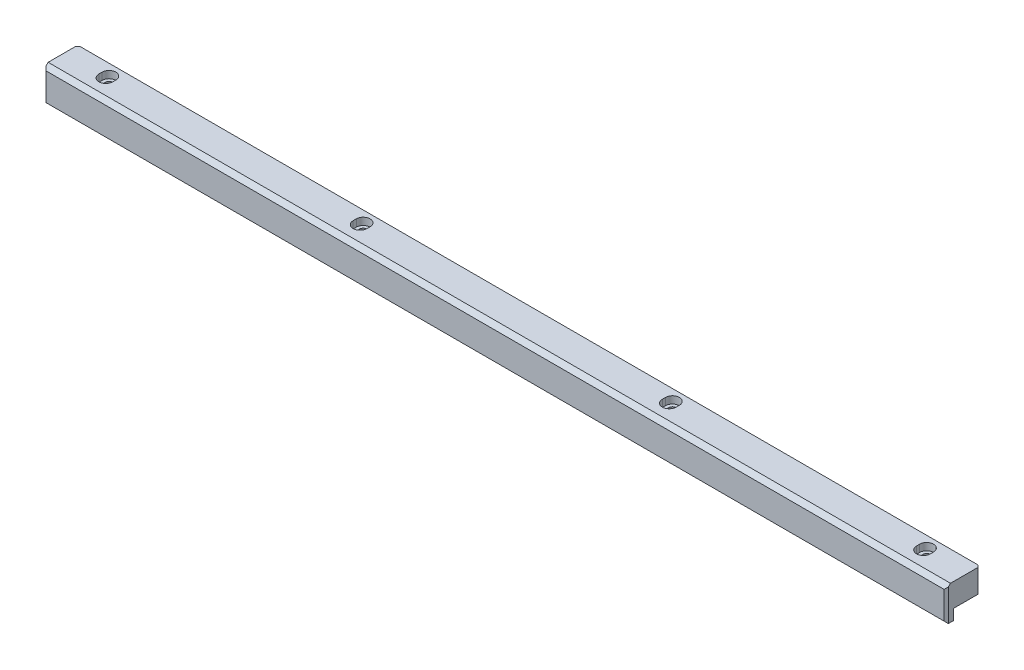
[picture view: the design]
ISO-10303-21;
HEADER;
FILE_DESCRIPTION(('STEP AP214'),'2;1');
FILE_NAME('part.step','',(''),(''),'','','');
FILE_SCHEMA(('AUTOMOTIVE_DESIGN { 1 0 10303 214 1 1 1 1 }'));
ENDSEC;
DATA;
#1=APPLICATION_CONTEXT('core data for automotive mechanical design processes');
#2=APPLICATION_PROTOCOL_DEFINITION('international standard','automotive_design',2000,#1);
#3=PRODUCT_CONTEXT('',#1,'mechanical');
#4=PRODUCT('Part','Part','',(#3));
#5=PRODUCT_RELATED_PRODUCT_CATEGORY('part','',(#4));
#6=PRODUCT_DEFINITION_FORMATION('','',#4);
#7=PRODUCT_DEFINITION_CONTEXT('part definition',#1,'design');
#8=PRODUCT_DEFINITION('design','',#6,#7);
#9=PRODUCT_DEFINITION_SHAPE('','',#8);
#10=(LENGTH_UNIT() NAMED_UNIT(*) SI_UNIT(.MILLI.,.METRE.));
#11=(NAMED_UNIT(*) PLANE_ANGLE_UNIT() SI_UNIT($,.RADIAN.));
#12=(NAMED_UNIT(*) SI_UNIT($,.STERADIAN.) SOLID_ANGLE_UNIT());
#13=UNCERTAINTY_MEASURE_WITH_UNIT(LENGTH_MEASURE(1.E-05),#10,'distance_accuracy_value','');
#14=(GEOMETRIC_REPRESENTATION_CONTEXT(3) GLOBAL_UNCERTAINTY_ASSIGNED_CONTEXT((#13)) GLOBAL_UNIT_ASSIGNED_CONTEXT((#10,
#11,#12)) REPRESENTATION_CONTEXT('',''));
#15=CARTESIAN_POINT('',(0.,0.,0.));
#16=DIRECTION('',(0.,0.,1.));
#17=DIRECTION('',(1.,0.,0.));
#18=AXIS2_PLACEMENT_3D('',#15,#16,#17);
#19=CARTESIAN_POINT('',(0.,16.,0.));
#20=DIRECTION('',(0.,1.,0.));
#21=DIRECTION('',(0.,0.,1.));
#22=AXIS2_PLACEMENT_3D('',#19,#20,#21);
#23=PLANE('',#22);
#24=DIRECTION('',(0.,0.,-1.));
#25=VECTOR('',#24,1.);
#26=CARTESIAN_POINT('',(189.75,16.,-1.25));
#27=LINE('',#26,#25);
#28=CARTESIAN_POINT('',(189.75,16.,-1.25));
#29=VERTEX_POINT('',#28);
#30=CARTESIAN_POINT('',(189.75,16.,-2.75));
#31=VERTEX_POINT('',#30);
#32=EDGE_CURVE('E654',#29,#31,#27,.T.);
#33=ORIENTED_EDGE('',*,*,#32,.T.);
#34=CARTESIAN_POINT('',(193.,16.,-2.75));
#35=DIRECTION('',(0.,1.,0.));
#36=DIRECTION('',(0.,0.,1.));
#37=AXIS2_PLACEMENT_3D('',#34,#35,#36);
#38=CIRCLE('',#37,3.25);
#39=CARTESIAN_POINT('',(196.25,16.,-2.75));
#40=VERTEX_POINT('',#39);
#41=EDGE_CURVE('E674',#40,#31,#38,.T.);
#42=ORIENTED_EDGE('',*,*,#41,.F.);
#43=DIRECTION('',(0.,0.,-1.));
#44=VECTOR('',#43,1.);
#45=CARTESIAN_POINT('',(196.25,16.,-1.25));
#46=LINE('',#45,#44);
#47=CARTESIAN_POINT('',(196.25,16.,-1.25));
#48=VERTEX_POINT('',#47);
#49=EDGE_CURVE('E640',#48,#40,#46,.T.);
#50=ORIENTED_EDGE('',*,*,#49,.F.);
#51=CARTESIAN_POINT('',(193.,16.,-1.25));
#52=DIRECTION('',(0.,1.,0.));
#53=DIRECTION('',(0.,0.,1.));
#54=AXIS2_PLACEMENT_3D('',#51,#52,#53);
#55=CIRCLE('',#54,3.25);
#56=EDGE_CURVE('E629',#29,#48,#55,.T.);
#57=ORIENTED_EDGE('',*,*,#56,.F.);
#58=EDGE_LOOP('',(#33,#42,#50,#57));
#59=FACE_BOUND('',#58,.T.);
#60=DIRECTION('',(0.,0.,-1.));
#61=VECTOR('',#60,1.);
#62=CARTESIAN_POINT('',(76.2499999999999,16.,-1.24999999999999));
#63=LINE('',#62,#61);
#64=CARTESIAN_POINT('',(76.2499999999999,16.,-1.24999999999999));
#65=VERTEX_POINT('',#64);
#66=CARTESIAN_POINT('',(76.2499999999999,16.,-2.74999999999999));
#67=VERTEX_POINT('',#66);
#68=EDGE_CURVE('E828',#65,#67,#63,.T.);
#69=ORIENTED_EDGE('',*,*,#68,.F.);
#70=CARTESIAN_POINT('',(72.9999999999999,16.,-1.24999999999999));
#71=DIRECTION('',(0.,1.,0.));
#72=DIRECTION('',(0.,0.,1.));
#73=AXIS2_PLACEMENT_3D('',#70,#71,#72);
#74=CIRCLE('',#73,3.25);
#75=CARTESIAN_POINT('',(69.7499999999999,16.,-1.24999999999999));
#76=VERTEX_POINT('',#75);
#77=EDGE_CURVE('E859',#76,#65,#74,.T.);
#78=ORIENTED_EDGE('',*,*,#77,.F.);
#79=DIRECTION('',(0.,0.,-1.));
#80=VECTOR('',#79,1.);
#81=CARTESIAN_POINT('',(69.7499999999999,16.,-1.24999999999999));
#82=LINE('',#81,#80);
#83=CARTESIAN_POINT('',(69.7499999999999,16.,-2.74999999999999));
#84=VERTEX_POINT('',#83);
#85=EDGE_CURVE('E844',#76,#84,#82,.T.);
#86=ORIENTED_EDGE('',*,*,#85,.T.);
#87=CARTESIAN_POINT('',(72.9999999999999,16.,-2.74999999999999));
#88=DIRECTION('',(0.,1.,0.));
#89=DIRECTION('',(0.,0.,1.));
#90=AXIS2_PLACEMENT_3D('',#87,#88,#89);
#91=CIRCLE('',#90,3.25);
#92=EDGE_CURVE('E882',#67,#84,#91,.T.);
#93=ORIENTED_EDGE('',*,*,#92,.F.);
#94=EDGE_LOOP('',(#69,#78,#86,#93));
#95=FACE_BOUND('',#94,.T.);
#96=DIRECTION('',(0.,0.,-1.));
#97=VECTOR('',#96,1.);
#98=CARTESIAN_POINT('',(213.,16.,-8.));
#99=LINE('',#98,#97);
#100=CARTESIAN_POINT('',(213.,16.,6.00000000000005));
#101=VERTEX_POINT('',#100);
#102=CARTESIAN_POINT('',(213.,16.,-6.99999999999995));
#103=VERTEX_POINT('',#102);
#104=EDGE_CURVE('E924',#101,#103,#99,.T.);
#105=ORIENTED_EDGE('',*,*,#104,.T.);
#106=DIRECTION('',(0.707106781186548,0.,0.707106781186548));
#107=VECTOR('',#106,1.);
#108=CARTESIAN_POINT('',(110.,16.,-110.));
#109=LINE('',#108,#107);
#110=CARTESIAN_POINT('',(212.,16.,-8.));
#111=VERTEX_POINT('',#110);
#112=EDGE_CURVE('E1050',#103,#111,#109,.F.);
#113=ORIENTED_EDGE('',*,*,#112,.T.);
#114=DIRECTION('',(-1.,0.,0.));
#115=VECTOR('',#114,1.);
#116=CARTESIAN_POINT('',(-213.,16.,-8.));
#117=LINE('',#116,#115);
#118=CARTESIAN_POINT('',(-212.,16.,-8.));
#119=VERTEX_POINT('',#118);
#120=EDGE_CURVE('E928',#111,#119,#117,.T.);
#121=ORIENTED_EDGE('',*,*,#120,.T.);
#122=DIRECTION('',(0.707106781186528,0.,-0.707106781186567));
#123=VECTOR('',#122,1.);
#124=CARTESIAN_POINT('',(-110.000000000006,16.,-110.));
#125=LINE('',#124,#123);
#126=CARTESIAN_POINT('',(-213.,16.,-7.));
#127=VERTEX_POINT('',#126);
#128=EDGE_CURVE('E1047',#119,#127,#125,.F.);
#129=ORIENTED_EDGE('',*,*,#128,.T.);
#130=DIRECTION('',(0.,0.,1.));
#131=VECTOR('',#130,1.);
#132=CARTESIAN_POINT('',(-213.,16.,-8.));
#133=LINE('',#132,#131);
#134=CARTESIAN_POINT('',(-213.,16.,6.00000000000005));
#135=VERTEX_POINT('',#134);
#136=EDGE_CURVE('E933',#127,#135,#133,.T.);
#137=ORIENTED_EDGE('',*,*,#136,.T.);
#138=DIRECTION('',(1.,0.,0.));
#139=VECTOR('',#138,1.);
#140=CARTESIAN_POINT('',(213.,16.,6.00000000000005));
#141=LINE('',#140,#139);
#142=EDGE_CURVE('E1013',#135,#101,#141,.T.);
#143=ORIENTED_EDGE('',*,*,#142,.T.);
#144=EDGE_LOOP('',(#105,#113,#121,#129,#137,#143));
#145=FACE_BOUND('',#144,.T.);
#146=CARTESIAN_POINT('',(-73.0000000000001,16.,-1.25));
#147=DIRECTION('',(0.,1.,0.));
#148=DIRECTION('',(0.,0.,1.));
#149=AXIS2_PLACEMENT_3D('',#146,#147,#148);
#150=CIRCLE('',#149,3.25);
#151=CARTESIAN_POINT('',(-76.2500000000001,16.,-1.25));
#152=VERTEX_POINT('',#151);
#153=CARTESIAN_POINT('',(-69.7500000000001,16.,-1.25));
#154=VERTEX_POINT('',#153);
#155=EDGE_CURVE('E790',#152,#154,#150,.T.);
#156=ORIENTED_EDGE('',*,*,#155,.F.);
#157=DIRECTION('',(0.,0.,-1.));
#158=VECTOR('',#157,1.);
#159=CARTESIAN_POINT('',(-76.2500000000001,16.,-1.25));
#160=LINE('',#159,#158);
#161=CARTESIAN_POINT('',(-76.2500000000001,16.,-2.75));
#162=VERTEX_POINT('',#161);
#163=EDGE_CURVE('E774',#152,#162,#160,.T.);
#164=ORIENTED_EDGE('',*,*,#163,.T.);
#165=CARTESIAN_POINT('',(-73.0000000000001,16.,-2.75));
#166=DIRECTION('',(0.,1.,0.));
#167=DIRECTION('',(0.,0.,1.));
#168=AXIS2_PLACEMENT_3D('',#165,#166,#167);
#169=CIRCLE('',#168,3.25);
#170=CARTESIAN_POINT('',(-69.7500000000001,16.,-2.75));
#171=VERTEX_POINT('',#170);
#172=EDGE_CURVE('E813',#171,#162,#169,.T.);
#173=ORIENTED_EDGE('',*,*,#172,.F.);
#174=DIRECTION('',(0.,0.,-1.));
#175=VECTOR('',#174,1.);
#176=CARTESIAN_POINT('',(-69.7500000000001,16.,-1.25));
#177=LINE('',#176,#175);
#178=EDGE_CURVE('E758',#154,#171,#177,.T.);
#179=ORIENTED_EDGE('',*,*,#178,.F.);
#180=EDGE_LOOP('',(#156,#164,#173,#179));
#181=FACE_BOUND('',#180,.T.);
#182=CARTESIAN_POINT('',(-193.,16.,-1.24999999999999));
#183=DIRECTION('',(0.,1.,0.));
#184=DIRECTION('',(0.,0.,1.));
#185=AXIS2_PLACEMENT_3D('',#182,#183,#184);
#186=CIRCLE('',#185,3.25);
#187=CARTESIAN_POINT('',(-196.25,16.,-1.24999999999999));
#188=VERTEX_POINT('',#187);
#189=CARTESIAN_POINT('',(-189.75,16.,-1.24999999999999));
#190=VERTEX_POINT('',#189);
#191=EDGE_CURVE('E720',#188,#190,#186,.T.);
#192=ORIENTED_EDGE('',*,*,#191,.F.);
#193=DIRECTION('',(0.,0.,-1.));
#194=VECTOR('',#193,1.);
#195=CARTESIAN_POINT('',(-196.25,16.,-1.24999999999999));
#196=LINE('',#195,#194);
#197=CARTESIAN_POINT('',(-196.25,16.,-2.74999999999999));
#198=VERTEX_POINT('',#197);
#199=EDGE_CURVE('E704',#188,#198,#196,.T.);
#200=ORIENTED_EDGE('',*,*,#199,.T.);
#201=CARTESIAN_POINT('',(-193.,16.,-2.74999999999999));
#202=DIRECTION('',(0.,1.,0.));
#203=DIRECTION('',(0.,0.,1.));
#204=AXIS2_PLACEMENT_3D('',#201,#202,#203);
#205=CIRCLE('',#204,3.25);
#206=CARTESIAN_POINT('',(-189.75,16.,-2.74999999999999));
#207=VERTEX_POINT('',#206);
#208=EDGE_CURVE('E743',#207,#198,#205,.T.);
#209=ORIENTED_EDGE('',*,*,#208,.F.);
#210=DIRECTION('',(0.,0.,-1.));
#211=VECTOR('',#210,1.);
#212=CARTESIAN_POINT('',(-189.75,16.,-1.24999999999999));
#213=LINE('',#212,#211);
#214=EDGE_CURVE('E688',#190,#207,#213,.T.);
#215=ORIENTED_EDGE('',*,*,#214,.F.);
#216=EDGE_LOOP('',(#192,#200,#209,#215));
#217=FACE_BOUND('',#216,.T.);
#218=ADVANCED_FACE('F339',(#59,#95,#145,#181,#217),#23,.T.);
#219=CARTESIAN_POINT('',(213.,16.,-8.));
#220=DIRECTION('',(-1.,0.,0.));
#221=DIRECTION('',(0.,0.,1.));
#222=AXIS2_PLACEMENT_3D('',#219,#220,#221);
#223=PLANE('',#222);
#224=DIRECTION('',(0.,0.,1.));
#225=VECTOR('',#224,1.);
#226=CARTESIAN_POINT('',(213.,5.,-8.));
#227=LINE('',#226,#225);
#228=CARTESIAN_POINT('',(213.,5.,-6.99999999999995));
#229=VERTEX_POINT('',#228);
#230=CARTESIAN_POINT('',(213.,5.,4.5));
#231=VERTEX_POINT('',#230);
#232=EDGE_CURVE('E906',#229,#231,#227,.T.);
#233=ORIENTED_EDGE('',*,*,#232,.F.);
#234=DIRECTION('',(0.,1.,0.));
#235=VECTOR('',#234,1.);
#236=CARTESIAN_POINT('',(213.,16.,-6.99999999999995));
#237=LINE('',#236,#235);
#238=EDGE_CURVE('E1044',#229,#103,#237,.T.);
#239=ORIENTED_EDGE('',*,*,#238,.T.);
#240=ORIENTED_EDGE('',*,*,#104,.F.);
#241=DIRECTION('',(0.,-0.707106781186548,0.707106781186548));
#242=VECTOR('',#241,1.);
#243=CARTESIAN_POINT('',(213.,16.,6.00000000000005));
#244=LINE('',#243,#242);
#245=CARTESIAN_POINT('',(213.,15.0000000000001,7.));
#246=VERTEX_POINT('',#245);
#247=EDGE_CURVE('E1017',#101,#246,#244,.T.);
#248=ORIENTED_EDGE('',*,*,#247,.T.);
#249=DIRECTION('',(0.,-1.,0.));
#250=VECTOR('',#249,1.);
#251=CARTESIAN_POINT('',(213.,16.,7.));
#252=LINE('',#251,#250);
#253=CARTESIAN_POINT('',(213.,0.,7.00000000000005));
#254=VERTEX_POINT('',#253);
#255=EDGE_CURVE('E1040',#246,#254,#252,.T.);
#256=ORIENTED_EDGE('',*,*,#255,.T.);
#257=DIRECTION('',(0.,0.,-1.));
#258=VECTOR('',#257,1.);
#259=CARTESIAN_POINT('',(213.,0.,-8.));
#260=LINE('',#259,#258);
#261=CARTESIAN_POINT('',(213.,0.,4.5));
#262=VERTEX_POINT('',#261);
#263=EDGE_CURVE('E920',#254,#262,#260,.T.);
#264=ORIENTED_EDGE('',*,*,#263,.T.);
#265=DIRECTION('',(0.,-1.,0.));
#266=VECTOR('',#265,1.);
#267=CARTESIAN_POINT('',(213.,5.,4.5));
#268=LINE('',#267,#266);
#269=EDGE_CURVE('E913',#231,#262,#268,.T.);
#270=ORIENTED_EDGE('',*,*,#269,.F.);
#271=EDGE_LOOP('',(#233,#239,#240,#248,#256,#264,#270));
#272=FACE_BOUND('',#271,.T.);
#273=ADVANCED_FACE('F1089',(#272),#223,.F.);
#274=CARTESIAN_POINT('',(-213.,16.,-8.));
#275=DIRECTION('',(0.,0.,1.));
#276=DIRECTION('',(1.,0.,0.));
#277=AXIS2_PLACEMENT_3D('',#274,#275,#276);
#278=PLANE('',#277);
#279=ORIENTED_EDGE('',*,*,#120,.F.);
#280=DIRECTION('',(0.,-1.,0.));
#281=VECTOR('',#280,1.);
#282=CARTESIAN_POINT('',(212.,16.,-8.));
#283=LINE('',#282,#281);
#284=CARTESIAN_POINT('',(212.,5.,-8.));
#285=VERTEX_POINT('',#284);
#286=EDGE_CURVE('E1030',#111,#285,#283,.T.);
#287=ORIENTED_EDGE('',*,*,#286,.T.);
#288=DIRECTION('',(1.,0.,0.));
#289=VECTOR('',#288,1.);
#290=CARTESIAN_POINT('',(-213.,5.,-8.));
#291=LINE('',#290,#289);
#292=CARTESIAN_POINT('',(-212.,5.,-8.));
#293=VERTEX_POINT('',#292);
#294=EDGE_CURVE('E902',#293,#285,#291,.T.);
#295=ORIENTED_EDGE('',*,*,#294,.F.);
#296=DIRECTION('',(0.,1.,0.));
#297=VECTOR('',#296,1.);
#298=CARTESIAN_POINT('',(-212.,16.,-8.));
#299=LINE('',#298,#297);
#300=EDGE_CURVE('E1027',#293,#119,#299,.T.);
#301=ORIENTED_EDGE('',*,*,#300,.T.);
#302=EDGE_LOOP('',(#279,#287,#295,#301));
#303=FACE_BOUND('',#302,.T.);
#304=ADVANCED_FACE('F1126',(#303),#278,.F.);
#305=CARTESIAN_POINT('',(-213.,16.,-8.));
#306=DIRECTION('',(1.,0.,0.));
#307=DIRECTION('',(0.,0.,-1.));
#308=AXIS2_PLACEMENT_3D('',#305,#306,#307);
#309=PLANE('',#308);
#310=DIRECTION('',(0.,0.,1.));
#311=VECTOR('',#310,1.);
#312=CARTESIAN_POINT('',(-213.,0.,-8.));
#313=LINE('',#312,#311);
#314=CARTESIAN_POINT('',(-213.,0.,4.5));
#315=VERTEX_POINT('',#314);
#316=CARTESIAN_POINT('',(-213.,0.,7.00000000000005));
#317=VERTEX_POINT('',#316);
#318=EDGE_CURVE('E929',#315,#317,#313,.T.);
#319=ORIENTED_EDGE('',*,*,#318,.T.);
#320=DIRECTION('',(0.,1.,0.));
#321=VECTOR('',#320,1.);
#322=CARTESIAN_POINT('',(-213.,16.,6.99999999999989));
#323=LINE('',#322,#321);
#324=CARTESIAN_POINT('',(-213.,15.0000000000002,6.99999999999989));
#325=VERTEX_POINT('',#324);
#326=EDGE_CURVE('E13',#317,#325,#323,.T.);
#327=ORIENTED_EDGE('',*,*,#326,.T.);
#328=DIRECTION('',(0.,0.707106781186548,-0.707106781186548));
#329=VECTOR('',#328,1.);
#330=CARTESIAN_POINT('',(-213.,16.,6.00000000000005));
#331=LINE('',#330,#329);
#332=EDGE_CURVE('E1024',#325,#135,#331,.T.);
#333=ORIENTED_EDGE('',*,*,#332,.T.);
#334=ORIENTED_EDGE('',*,*,#136,.F.);
#335=DIRECTION('',(0.,-1.,0.));
#336=VECTOR('',#335,1.);
#337=CARTESIAN_POINT('',(-213.,16.,-7.));
#338=LINE('',#337,#336);
#339=CARTESIAN_POINT('',(-213.,5.,-7.));
#340=VERTEX_POINT('',#339);
#341=EDGE_CURVE('E349',#127,#340,#338,.T.);
#342=ORIENTED_EDGE('',*,*,#341,.T.);
#343=DIRECTION('',(0.,0.,-1.));
#344=VECTOR('',#343,1.);
#345=CARTESIAN_POINT('',(-213.,5.,-8.));
#346=LINE('',#345,#344);
#347=CARTESIAN_POINT('',(-213.,5.,4.5));
#348=VERTEX_POINT('',#347);
#349=EDGE_CURVE('E898',#348,#340,#346,.T.);
#350=ORIENTED_EDGE('',*,*,#349,.F.);
#351=DIRECTION('',(0.,-1.,0.));
#352=VECTOR('',#351,1.);
#353=CARTESIAN_POINT('',(-213.,5.,4.5));
#354=LINE('',#353,#352);
#355=EDGE_CURVE('E916',#348,#315,#354,.T.);
#356=ORIENTED_EDGE('',*,*,#355,.T.);
#357=EDGE_LOOP('',(#319,#327,#333,#334,#342,#350,#356));
#358=FACE_BOUND('',#357,.T.);
#359=ADVANCED_FACE('F1076',(#358),#309,.F.);
#360=CARTESIAN_POINT('',(-213.,16.,8.));
#361=DIRECTION('',(0.,0.,-1.));
#362=DIRECTION('',(-1.,0.,0.));
#363=AXIS2_PLACEMENT_3D('',#360,#361,#362);
#364=PLANE('',#363);
#365=DIRECTION('',(1.,0.,0.));
#366=VECTOR('',#365,1.);
#367=CARTESIAN_POINT('',(-213.,1.,8.));
#368=LINE('',#367,#366);
#369=CARTESIAN_POINT('',(-212.,1.,8.));
#370=VERTEX_POINT('',#369);
#371=CARTESIAN_POINT('',(212.,1.,8.));
#372=VERTEX_POINT('',#371);
#373=EDGE_CURVE('E937',#370,#372,#368,.T.);
#374=ORIENTED_EDGE('',*,*,#373,.T.);
#375=DIRECTION('',(0.,1.,0.));
#376=VECTOR('',#375,1.);
#377=CARTESIAN_POINT('',(212.,16.,8.));
#378=LINE('',#377,#376);
#379=CARTESIAN_POINT('',(212.,14.0000000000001,8.));
#380=VERTEX_POINT('',#379);
#381=EDGE_CURVE('E1063',#372,#380,#378,.T.);
#382=ORIENTED_EDGE('',*,*,#381,.T.);
#383=DIRECTION('',(-1.,0.,0.));
#384=VECTOR('',#383,1.);
#385=CARTESIAN_POINT('',(-213.,14.0000000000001,8.));
#386=LINE('',#385,#384);
#387=CARTESIAN_POINT('',(-212.,14.0000000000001,8.));
#388=VERTEX_POINT('',#387);
#389=EDGE_CURVE('E1021',#380,#388,#386,.T.);
#390=ORIENTED_EDGE('',*,*,#389,.T.);
#391=DIRECTION('',(0.,-1.,0.));
#392=VECTOR('',#391,1.);
#393=CARTESIAN_POINT('',(-212.,16.,8.));
#394=LINE('',#393,#392);
#395=EDGE_CURVE('E1059',#388,#370,#394,.T.);
#396=ORIENTED_EDGE('',*,*,#395,.T.);
#397=EDGE_LOOP('',(#374,#382,#390,#396));
#398=FACE_BOUND('',#397,.T.);
#399=ADVANCED_FACE('F1104',(#398),#364,.F.);
#400=CARTESIAN_POINT('',(0.,0.,0.));
#401=DIRECTION('',(0.,1.,0.));
#402=DIRECTION('',(0.,0.,1.));
#403=AXIS2_PLACEMENT_3D('',#400,#401,#402);
#404=PLANE('',#403);
#405=ORIENTED_EDGE('',*,*,#263,.F.);
#406=DIRECTION('',(-1.,0.,0.));
#407=VECTOR('',#406,1.);
#408=CARTESIAN_POINT('',(0.,0.,7.00000000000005));
#409=LINE('',#408,#407);
#410=EDGE_CURVE('E945',#254,#317,#409,.T.);
#411=ORIENTED_EDGE('',*,*,#410,.T.);
#412=ORIENTED_EDGE('',*,*,#318,.F.);
#413=DIRECTION('',(-1.,0.,0.));
#414=VECTOR('',#413,1.);
#415=CARTESIAN_POINT('',(-213.,0.,4.5));
#416=LINE('',#415,#414);
#417=EDGE_CURVE('E897',#262,#315,#416,.T.);
#418=ORIENTED_EDGE('',*,*,#417,.F.);
#419=EDGE_LOOP('',(#405,#411,#412,#418));
#420=FACE_BOUND('',#419,.T.);
#421=ADVANCED_FACE('F1095',(#420),#404,.F.);
#422=CARTESIAN_POINT('',(-213.,5.,4.5));
#423=DIRECTION('',(0.,0.,1.));
#424=DIRECTION('',(1.,0.,0.));
#425=AXIS2_PLACEMENT_3D('',#422,#423,#424);
#426=PLANE('',#425);
#427=ORIENTED_EDGE('',*,*,#417,.T.);
#428=ORIENTED_EDGE('',*,*,#355,.F.);
#429=DIRECTION('',(-1.,0.,0.));
#430=VECTOR('',#429,1.);
#431=CARTESIAN_POINT('',(-213.,5.,4.5));
#432=LINE('',#431,#430);
#433=EDGE_CURVE('E909',#231,#348,#432,.T.);
#434=ORIENTED_EDGE('',*,*,#433,.F.);
#435=ORIENTED_EDGE('',*,*,#269,.T.);
#436=EDGE_LOOP('',(#427,#428,#434,#435));
#437=FACE_BOUND('',#436,.T.);
#438=ADVANCED_FACE('F1086',(#437),#426,.F.);
#439=CARTESIAN_POINT('',(0.,5.,0.));
#440=DIRECTION('',(0.,1.,0.));
#441=DIRECTION('',(0.,0.,1.));
#442=AXIS2_PLACEMENT_3D('',#439,#440,#441);
#443=PLANE('',#442);
#444=CARTESIAN_POINT('',(193.,5.,-1.25));
#445=DIRECTION('',(0.,1.,0.));
#446=DIRECTION('',(0.,0.,1.));
#447=AXIS2_PLACEMENT_3D('',#444,#445,#446);
#448=CIRCLE('',#447,1.70000000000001);
#449=CARTESIAN_POINT('',(191.3,5.,-1.25));
#450=VERTEX_POINT('',#449);
#451=CARTESIAN_POINT('',(194.7,5.,-1.25));
#452=VERTEX_POINT('',#451);
#453=EDGE_CURVE('E1001',#450,#452,#448,.T.);
#454=ORIENTED_EDGE('',*,*,#453,.T.);
#455=DIRECTION('',(0.,0.,-1.));
#456=VECTOR('',#455,1.);
#457=CARTESIAN_POINT('',(194.7,5.,0.));
#458=LINE('',#457,#456);
#459=CARTESIAN_POINT('',(194.7,5.,-2.75));
#460=VERTEX_POINT('',#459);
#461=EDGE_CURVE('E1009',#452,#460,#458,.T.);
#462=ORIENTED_EDGE('',*,*,#461,.T.);
#463=CARTESIAN_POINT('',(193.,5.,-2.75));
#464=DIRECTION('',(0.,1.,0.));
#465=DIRECTION('',(0.,0.,1.));
#466=AXIS2_PLACEMENT_3D('',#463,#464,#465);
#467=CIRCLE('',#466,1.70000000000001);
#468=CARTESIAN_POINT('',(191.3,5.,-2.75));
#469=VERTEX_POINT('',#468);
#470=EDGE_CURVE('E1005',#460,#469,#467,.T.);
#471=ORIENTED_EDGE('',*,*,#470,.T.);
#472=DIRECTION('',(0.,0.,1.));
#473=VECTOR('',#472,1.);
#474=CARTESIAN_POINT('',(191.3,5.,0.));
#475=LINE('',#474,#473);
#476=EDGE_CURVE('E997',#469,#450,#475,.T.);
#477=ORIENTED_EDGE('',*,*,#476,.T.);
#478=EDGE_LOOP('',(#454,#462,#471,#477));
#479=FACE_BOUND('',#478,.T.);
#480=CARTESIAN_POINT('',(-193.,5.,-2.74999999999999));
#481=DIRECTION('',(0.,1.,0.));
#482=DIRECTION('',(0.,0.,1.));
#483=AXIS2_PLACEMENT_3D('',#480,#481,#482);
#484=CIRCLE('',#483,1.70000000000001);
#485=CARTESIAN_POINT('',(-191.3,5.,-2.74999999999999));
#486=VERTEX_POINT('',#485);
#487=CARTESIAN_POINT('',(-194.7,5.,-2.74999999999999));
#488=VERTEX_POINT('',#487);
#489=EDGE_CURVE('E985',#486,#488,#484,.T.);
#490=ORIENTED_EDGE('',*,*,#489,.T.);
#491=DIRECTION('',(0.,0.,1.));
#492=VECTOR('',#491,1.);
#493=CARTESIAN_POINT('',(-194.7,5.,0.));
#494=LINE('',#493,#492);
#495=CARTESIAN_POINT('',(-194.7,5.,-1.24999999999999));
#496=VERTEX_POINT('',#495);
#497=EDGE_CURVE('E993',#488,#496,#494,.T.);
#498=ORIENTED_EDGE('',*,*,#497,.T.);
#499=CARTESIAN_POINT('',(-193.,5.,-1.24999999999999));
#500=DIRECTION('',(0.,1.,0.));
#501=DIRECTION('',(0.,0.,1.));
#502=AXIS2_PLACEMENT_3D('',#499,#500,#501);
#503=CIRCLE('',#502,1.70000000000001);
#504=CARTESIAN_POINT('',(-191.3,5.,-1.24999999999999));
#505=VERTEX_POINT('',#504);
#506=EDGE_CURVE('E989',#496,#505,#503,.T.);
#507=ORIENTED_EDGE('',*,*,#506,.T.);
#508=DIRECTION('',(0.,0.,-1.));
#509=VECTOR('',#508,1.);
#510=CARTESIAN_POINT('',(-191.3,5.,0.));
#511=LINE('',#510,#509);
#512=EDGE_CURVE('E981',#505,#486,#511,.T.);
#513=ORIENTED_EDGE('',*,*,#512,.T.);
#514=EDGE_LOOP('',(#490,#498,#507,#513));
#515=FACE_BOUND('',#514,.T.);
#516=CARTESIAN_POINT('',(-73.0000000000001,5.,-2.75));
#517=DIRECTION('',(0.,1.,0.));
#518=DIRECTION('',(0.,0.,1.));
#519=AXIS2_PLACEMENT_3D('',#516,#517,#518);
#520=CIRCLE('',#519,1.69999999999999);
#521=CARTESIAN_POINT('',(-71.3000000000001,5.,-2.75));
#522=VERTEX_POINT('',#521);
#523=CARTESIAN_POINT('',(-74.7000000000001,5.,-2.75));
#524=VERTEX_POINT('',#523);
#525=EDGE_CURVE('E969',#522,#524,#520,.T.);
#526=ORIENTED_EDGE('',*,*,#525,.T.);
#527=DIRECTION('',(0.,0.,1.));
#528=VECTOR('',#527,1.);
#529=CARTESIAN_POINT('',(-74.7000000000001,5.,0.));
#530=LINE('',#529,#528);
#531=CARTESIAN_POINT('',(-74.7000000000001,5.,-1.25));
#532=VERTEX_POINT('',#531);
#533=EDGE_CURVE('E977',#524,#532,#530,.T.);
#534=ORIENTED_EDGE('',*,*,#533,.T.);
#535=CARTESIAN_POINT('',(-73.0000000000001,5.,-1.25));
#536=DIRECTION('',(0.,1.,0.));
#537=DIRECTION('',(0.,0.,1.));
#538=AXIS2_PLACEMENT_3D('',#535,#536,#537);
#539=CIRCLE('',#538,1.69999999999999);
#540=CARTESIAN_POINT('',(-71.3000000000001,5.,-1.25));
#541=VERTEX_POINT('',#540);
#542=EDGE_CURVE('E973',#532,#541,#539,.T.);
#543=ORIENTED_EDGE('',*,*,#542,.T.);
#544=DIRECTION('',(0.,0.,-1.));
#545=VECTOR('',#544,1.);
#546=CARTESIAN_POINT('',(-71.3000000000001,5.,0.));
#547=LINE('',#546,#545);
#548=EDGE_CURVE('E965',#541,#522,#547,.T.);
#549=ORIENTED_EDGE('',*,*,#548,.T.);
#550=EDGE_LOOP('',(#526,#534,#543,#549));
#551=FACE_BOUND('',#550,.T.);
#552=DIRECTION('',(0.,0.,1.));
#553=VECTOR('',#552,1.);
#554=CARTESIAN_POINT('',(71.2999999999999,5.,0.));
#555=LINE('',#554,#553);
#556=CARTESIAN_POINT('',(71.2999999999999,5.,-2.74999999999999));
#557=VERTEX_POINT('',#556);
#558=CARTESIAN_POINT('',(71.2999999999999,5.,-1.24999999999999));
#559=VERTEX_POINT('',#558);
#560=EDGE_CURVE('E949',#557,#559,#555,.T.);
#561=ORIENTED_EDGE('',*,*,#560,.T.);
#562=CARTESIAN_POINT('',(72.9999999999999,5.,-1.24999999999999));
#563=DIRECTION('',(0.,1.,0.));
#564=DIRECTION('',(0.,0.,1.));
#565=AXIS2_PLACEMENT_3D('',#562,#563,#564);
#566=CIRCLE('',#565,1.69999999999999);
#567=CARTESIAN_POINT('',(74.6999999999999,5.,-1.24999999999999));
#568=VERTEX_POINT('',#567);
#569=EDGE_CURVE('E961',#559,#568,#566,.T.);
#570=ORIENTED_EDGE('',*,*,#569,.T.);
#571=DIRECTION('',(0.,0.,-1.));
#572=VECTOR('',#571,1.);
#573=CARTESIAN_POINT('',(74.6999999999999,5.,0.));
#574=LINE('',#573,#572);
#575=CARTESIAN_POINT('',(74.6999999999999,5.,-2.74999999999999));
#576=VERTEX_POINT('',#575);
#577=EDGE_CURVE('E957',#568,#576,#574,.T.);
#578=ORIENTED_EDGE('',*,*,#577,.T.);
#579=CARTESIAN_POINT('',(72.9999999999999,5.,-2.74999999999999));
#580=DIRECTION('',(0.,1.,0.));
#581=DIRECTION('',(0.,0.,1.));
#582=AXIS2_PLACEMENT_3D('',#579,#580,#581);
#583=CIRCLE('',#582,1.69999999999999);
#584=EDGE_CURVE('E953',#576,#557,#583,.T.);
#585=ORIENTED_EDGE('',*,*,#584,.T.);
#586=EDGE_LOOP('',(#561,#570,#578,#585));
#587=FACE_BOUND('',#586,.T.);
#588=ORIENTED_EDGE('',*,*,#294,.T.);
#589=DIRECTION('',(-0.707106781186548,0.,-0.707106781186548));
#590=VECTOR('',#589,1.);
#591=CARTESIAN_POINT('',(212.,5.,-8.));
#592=LINE('',#591,#590);
#593=EDGE_CURVE('E1037',#285,#229,#592,.F.);
#594=ORIENTED_EDGE('',*,*,#593,.T.);
#595=ORIENTED_EDGE('',*,*,#232,.T.);
#596=ORIENTED_EDGE('',*,*,#433,.T.);
#597=ORIENTED_EDGE('',*,*,#349,.T.);
#598=DIRECTION('',(-0.707106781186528,0.,0.707106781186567));
#599=VECTOR('',#598,1.);
#600=CARTESIAN_POINT('',(-213.,5.,-7.));
#601=LINE('',#600,#599);
#602=EDGE_CURVE('E1034',#340,#293,#601,.F.);
#603=ORIENTED_EDGE('',*,*,#602,.T.);
#604=EDGE_LOOP('',(#588,#594,#595,#596,#597,#603));
#605=FACE_BOUND('',#604,.T.);
#606=ADVANCED_FACE('F1080',(#479,#515,#551,#587,#605),#443,.F.);
#607=CARTESIAN_POINT('',(-213.,1.,8.));
#608=DIRECTION('',(0.,0.707106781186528,-0.707106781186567));
#609=DIRECTION('',(1.,0.,0.));
#610=AXIS2_PLACEMENT_3D('',#607,#608,#609);
#611=PLANE('',#610);
#612=ORIENTED_EDGE('',*,*,#410,.F.);
#613=DIRECTION('',(-0.577350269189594,0.577350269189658,0.577350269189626));
#614=VECTOR('',#613,1.);
#615=CARTESIAN_POINT('',(70.333333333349,142.666666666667,149.666666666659));
#616=LINE('',#615,#614);
#617=EDGE_CURVE('E1056',#254,#372,#616,.T.);
#618=ORIENTED_EDGE('',*,*,#617,.T.);
#619=ORIENTED_EDGE('',*,*,#373,.F.);
#620=DIRECTION('',(-0.577350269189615,-0.577350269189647,-0.577350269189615));
#621=VECTOR('',#620,1.);
#622=CARTESIAN_POINT('',(-212.333333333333,0.666666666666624,7.66666666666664));
#623=LINE('',#622,#621);
#624=EDGE_CURVE('E1053',#370,#317,#623,.T.);
#625=ORIENTED_EDGE('',*,*,#624,.T.);
#626=EDGE_LOOP('',(#612,#618,#619,#625));
#627=FACE_BOUND('',#626,.T.);
#628=ADVANCED_FACE('F1098',(#627),#611,.F.);
#629=CARTESIAN_POINT('',(72.9999999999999,16.,-1.24999999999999));
#630=DIRECTION('',(0.,1.,0.));
#631=DIRECTION('',(0.,0.,1.));
#632=AXIS2_PLACEMENT_3D('',#629,#630,#631);
#633=CYLINDRICAL_SURFACE('',#632,1.69999999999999);
#634=DIRECTION('',(0.,1.,0.));
#635=VECTOR('',#634,1.);
#636=CARTESIAN_POINT('',(71.2999999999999,16.,-1.24999999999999));
#637=LINE('',#636,#635);
#638=CARTESIAN_POINT('',(71.2999999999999,12.6,-1.24999999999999));
#639=VERTEX_POINT('',#638);
#640=EDGE_CURVE('E848',#639,#559,#637,.F.);
#641=ORIENTED_EDGE('',*,*,#640,.F.);
#642=CARTESIAN_POINT('',(72.9999999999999,12.6,-1.24999999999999));
#643=DIRECTION('',(0.,1.,0.));
#644=DIRECTION('',(0.,0.,1.));
#645=AXIS2_PLACEMENT_3D('',#642,#643,#644);
#646=CIRCLE('',#645,1.69999999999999);
#647=CARTESIAN_POINT('',(74.6999999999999,12.6,-1.24999999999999));
#648=VERTEX_POINT('',#647);
#649=EDGE_CURVE('E865',#639,#648,#646,.T.);
#650=ORIENTED_EDGE('',*,*,#649,.T.);
#651=DIRECTION('',(0.,-1.,0.));
#652=VECTOR('',#651,1.);
#653=CARTESIAN_POINT('',(74.6999999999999,0.,-1.24999999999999));
#654=LINE('',#653,#652);
#655=EDGE_CURVE('E855',#648,#568,#654,.T.);
#656=ORIENTED_EDGE('',*,*,#655,.T.);
#657=ORIENTED_EDGE('',*,*,#569,.F.);
#658=EDGE_LOOP('',(#641,#650,#656,#657));
#659=FACE_BOUND('',#658,.T.);
#660=ADVANCED_FACE('F1148',(#659),#633,.F.);
#661=CARTESIAN_POINT('',(74.6999999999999,0.,-1.24999999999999));
#662=DIRECTION('',(1.,0.,0.));
#663=DIRECTION('',(0.,1.,0.));
#664=AXIS2_PLACEMENT_3D('',#661,#662,#663);
#665=PLANE('',#664);
#666=ORIENTED_EDGE('',*,*,#655,.F.);
#667=DIRECTION('',(0.,0.,-1.));
#668=VECTOR('',#667,1.);
#669=CARTESIAN_POINT('',(74.6999999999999,12.6,-1.24999999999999));
#670=LINE('',#669,#668);
#671=CARTESIAN_POINT('',(74.6999999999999,12.6,-2.74999999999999));
#672=VERTEX_POINT('',#671);
#673=EDGE_CURVE('E834',#648,#672,#670,.T.);
#674=ORIENTED_EDGE('',*,*,#673,.T.);
#675=DIRECTION('',(0.,-1.,0.));
#676=VECTOR('',#675,1.);
#677=CARTESIAN_POINT('',(74.6999999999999,0.,-2.74999999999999));
#678=LINE('',#677,#676);
#679=EDGE_CURVE('E878',#672,#576,#678,.T.);
#680=ORIENTED_EDGE('',*,*,#679,.T.);
#681=ORIENTED_EDGE('',*,*,#577,.F.);
#682=EDGE_LOOP('',(#666,#674,#680,#681));
#683=FACE_BOUND('',#682,.T.);
#684=ADVANCED_FACE('F1274',(#683),#665,.F.);
#685=CARTESIAN_POINT('',(72.9999999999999,16.,-2.74999999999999));
#686=DIRECTION('',(0.,1.,0.));
#687=DIRECTION('',(0.,0.,1.));
#688=AXIS2_PLACEMENT_3D('',#685,#686,#687);
#689=CYLINDRICAL_SURFACE('',#688,1.69999999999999);
#690=ORIENTED_EDGE('',*,*,#679,.F.);
#691=CARTESIAN_POINT('',(72.9999999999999,12.6,-2.74999999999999));
#692=DIRECTION('',(0.,1.,0.));
#693=DIRECTION('',(0.,0.,1.));
#694=AXIS2_PLACEMENT_3D('',#691,#692,#693);
#695=CIRCLE('',#694,1.69999999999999);
#696=CARTESIAN_POINT('',(71.2999999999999,12.6,-2.74999999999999));
#697=VERTEX_POINT('',#696);
#698=EDGE_CURVE('E889',#672,#697,#695,.T.);
#699=ORIENTED_EDGE('',*,*,#698,.T.);
#700=DIRECTION('',(0.,1.,0.));
#701=VECTOR('',#700,1.);
#702=CARTESIAN_POINT('',(71.2999999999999,16.,-2.74999999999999));
#703=LINE('',#702,#701);
#704=EDGE_CURVE('E871',#557,#697,#703,.T.);
#705=ORIENTED_EDGE('',*,*,#704,.F.);
#706=ORIENTED_EDGE('',*,*,#584,.F.);
#707=EDGE_LOOP('',(#690,#699,#705,#706));
#708=FACE_BOUND('',#707,.T.);
#709=ADVANCED_FACE('F1277',(#708),#689,.F.);
#710=CARTESIAN_POINT('',(71.2999999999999,16.,-1.24999999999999));
#711=DIRECTION('',(-1.,0.,0.));
#712=DIRECTION('',(0.,0.,1.));
#713=AXIS2_PLACEMENT_3D('',#710,#711,#712);
#714=PLANE('',#713);
#715=ORIENTED_EDGE('',*,*,#704,.T.);
#716=DIRECTION('',(0.,0.,-1.));
#717=VECTOR('',#716,1.);
#718=CARTESIAN_POINT('',(71.2999999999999,12.6,-1.24999999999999));
#719=LINE('',#718,#717);
#720=EDGE_CURVE('E837',#639,#697,#719,.T.);
#721=ORIENTED_EDGE('',*,*,#720,.F.);
#722=ORIENTED_EDGE('',*,*,#640,.T.);
#723=ORIENTED_EDGE('',*,*,#560,.F.);
#724=EDGE_LOOP('',(#715,#721,#722,#723));
#725=FACE_BOUND('',#724,.T.);
#726=ADVANCED_FACE('F1279',(#725),#714,.F.);
#727=CARTESIAN_POINT('',(74.6999999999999,12.6,-2.74999999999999));
#728=DIRECTION('',(0.,-1.,0.));
#729=DIRECTION('',(0.,0.,-1.));
#730=AXIS2_PLACEMENT_3D('',#727,#728,#729);
#731=PLANE('',#730);
#732=DIRECTION('',(0.,0.,-1.));
#733=VECTOR('',#732,1.);
#734=CARTESIAN_POINT('',(69.7499999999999,12.6,-1.24999999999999));
#735=LINE('',#734,#733);
#736=CARTESIAN_POINT('',(69.7499999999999,12.6,-1.24999999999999));
#737=VERTEX_POINT('',#736);
#738=CARTESIAN_POINT('',(69.7499999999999,12.6,-2.74999999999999));
#739=VERTEX_POINT('',#738);
#740=EDGE_CURVE('E841',#737,#739,#735,.T.);
#741=ORIENTED_EDGE('',*,*,#740,.F.);
#742=CARTESIAN_POINT('',(72.9999999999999,12.6,-1.24999999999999));
#743=DIRECTION('',(0.,1.,0.));
#744=DIRECTION('',(0.,0.,1.));
#745=AXIS2_PLACEMENT_3D('',#742,#743,#744);
#746=CIRCLE('',#745,3.25);
#747=CARTESIAN_POINT('',(76.2499999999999,12.6,-1.24999999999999));
#748=VERTEX_POINT('',#747);
#749=EDGE_CURVE('E862',#737,#748,#746,.T.);
#750=ORIENTED_EDGE('',*,*,#749,.T.);
#751=DIRECTION('',(0.,0.,-1.));
#752=VECTOR('',#751,1.);
#753=CARTESIAN_POINT('',(76.2499999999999,12.6,-1.24999999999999));
#754=LINE('',#753,#752);
#755=CARTESIAN_POINT('',(76.2499999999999,12.6,-2.74999999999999));
#756=VERTEX_POINT('',#755);
#757=EDGE_CURVE('E831',#748,#756,#754,.T.);
#758=ORIENTED_EDGE('',*,*,#757,.T.);
#759=CARTESIAN_POINT('',(72.9999999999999,12.6,-2.74999999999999));
#760=DIRECTION('',(0.,1.,0.));
#761=DIRECTION('',(0.,0.,1.));
#762=AXIS2_PLACEMENT_3D('',#759,#760,#761);
#763=CIRCLE('',#762,3.25);
#764=EDGE_CURVE('E885',#756,#739,#763,.T.);
#765=ORIENTED_EDGE('',*,*,#764,.T.);
#766=EDGE_LOOP('',(#741,#750,#758,#765));
#767=FACE_BOUND('',#766,.T.);
#768=ORIENTED_EDGE('',*,*,#698,.F.);
#769=ORIENTED_EDGE('',*,*,#673,.F.);
#770=ORIENTED_EDGE('',*,*,#649,.F.);
#771=ORIENTED_EDGE('',*,*,#720,.T.);
#772=EDGE_LOOP('',(#768,#769,#770,#771));
#773=FACE_BOUND('',#772,.T.);
#774=ADVANCED_FACE('F1282',(#767,#773),#731,.F.);
#775=CARTESIAN_POINT('',(72.9999999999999,16.,-2.74999999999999));
#776=DIRECTION('',(0.,1.,0.));
#777=DIRECTION('',(0.,0.,1.));
#778=AXIS2_PLACEMENT_3D('',#775,#776,#777);
#779=CYLINDRICAL_SURFACE('',#778,3.25);
#780=ORIENTED_EDGE('',*,*,#764,.F.);
#781=DIRECTION('',(0.,-1.,0.));
#782=VECTOR('',#781,1.);
#783=CARTESIAN_POINT('',(76.2499999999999,12.6,-2.74999999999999));
#784=LINE('',#783,#782);
#785=EDGE_CURVE('E874',#67,#756,#784,.T.);
#786=ORIENTED_EDGE('',*,*,#785,.F.);
#787=ORIENTED_EDGE('',*,*,#92,.T.);
#788=DIRECTION('',(0.,1.,0.));
#789=VECTOR('',#788,1.);
#790=CARTESIAN_POINT('',(69.7499999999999,16.,-2.74999999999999));
#791=LINE('',#790,#789);
#792=EDGE_CURVE('E893',#739,#84,#791,.T.);
#793=ORIENTED_EDGE('',*,*,#792,.F.);
#794=EDGE_LOOP('',(#780,#786,#787,#793));
#795=FACE_BOUND('',#794,.T.);
#796=ADVANCED_FACE('F1290',(#795),#779,.F.);
#797=CARTESIAN_POINT('',(72.9999999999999,16.,-1.24999999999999));
#798=DIRECTION('',(0.,1.,0.));
#799=DIRECTION('',(0.,0.,1.));
#800=AXIS2_PLACEMENT_3D('',#797,#798,#799);
#801=CYLINDRICAL_SURFACE('',#800,3.25);
#802=ORIENTED_EDGE('',*,*,#77,.T.);
#803=DIRECTION('',(0.,-1.,0.));
#804=VECTOR('',#803,1.);
#805=CARTESIAN_POINT('',(76.2499999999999,12.6,-1.24999999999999));
#806=LINE('',#805,#804);
#807=EDGE_CURVE('E851',#65,#748,#806,.T.);
#808=ORIENTED_EDGE('',*,*,#807,.T.);
#809=ORIENTED_EDGE('',*,*,#749,.F.);
#810=DIRECTION('',(0.,1.,0.));
#811=VECTOR('',#810,1.);
#812=CARTESIAN_POINT('',(69.7499999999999,16.,-1.24999999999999));
#813=LINE('',#812,#811);
#814=EDGE_CURVE('E868',#76,#737,#813,.F.);
#815=ORIENTED_EDGE('',*,*,#814,.F.);
#816=EDGE_LOOP('',(#802,#808,#809,#815));
#817=FACE_BOUND('',#816,.T.);
#818=ADVANCED_FACE('F1286',(#817),#801,.F.);
#819=CARTESIAN_POINT('',(69.7499999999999,16.,-1.24999999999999));
#820=DIRECTION('',(-1.,0.,0.));
#821=DIRECTION('',(0.,0.,1.));
#822=AXIS2_PLACEMENT_3D('',#819,#820,#821);
#823=PLANE('',#822);
#824=ORIENTED_EDGE('',*,*,#792,.T.);
#825=ORIENTED_EDGE('',*,*,#85,.F.);
#826=ORIENTED_EDGE('',*,*,#814,.T.);
#827=ORIENTED_EDGE('',*,*,#740,.T.);
#828=EDGE_LOOP('',(#824,#825,#826,#827));
#829=FACE_BOUND('',#828,.T.);
#830=ADVANCED_FACE('F1272',(#829),#823,.F.);
#831=CARTESIAN_POINT('',(76.2499999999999,12.6,-1.24999999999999));
#832=DIRECTION('',(1.,0.,0.));
#833=DIRECTION('',(0.,0.,-1.));
#834=AXIS2_PLACEMENT_3D('',#831,#832,#833);
#835=PLANE('',#834);
#836=ORIENTED_EDGE('',*,*,#785,.T.);
#837=ORIENTED_EDGE('',*,*,#757,.F.);
#838=ORIENTED_EDGE('',*,*,#807,.F.);
#839=ORIENTED_EDGE('',*,*,#68,.T.);
#840=EDGE_LOOP('',(#836,#837,#838,#839));
#841=FACE_BOUND('',#840,.T.);
#842=ADVANCED_FACE('F1259',(#841),#835,.F.);
#843=CARTESIAN_POINT('',(-73.0000000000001,16.,-1.25));
#844=DIRECTION('',(0.,1.,0.));
#845=DIRECTION('',(0.,0.,1.));
#846=AXIS2_PLACEMENT_3D('',#843,#844,#845);
#847=CYLINDRICAL_SURFACE('',#846,1.69999999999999);
#848=DIRECTION('',(0.,1.,0.));
#849=VECTOR('',#848,1.);
#850=CARTESIAN_POINT('',(-74.7000000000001,16.,-1.25));
#851=LINE('',#850,#849);
#852=CARTESIAN_POINT('',(-74.7000000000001,12.6,-1.25));
#853=VERTEX_POINT('',#852);
#854=EDGE_CURVE('E778',#853,#532,#851,.F.);
#855=ORIENTED_EDGE('',*,*,#854,.F.);
#856=CARTESIAN_POINT('',(-73.0000000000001,12.6,-1.25));
#857=DIRECTION('',(0.,1.,0.));
#858=DIRECTION('',(0.,0.,1.));
#859=AXIS2_PLACEMENT_3D('',#856,#857,#858);
#860=CIRCLE('',#859,1.69999999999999);
#861=CARTESIAN_POINT('',(-71.3000000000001,12.6,-1.25));
#862=VERTEX_POINT('',#861);
#863=EDGE_CURVE('E797',#853,#862,#860,.T.);
#864=ORIENTED_EDGE('',*,*,#863,.T.);
#865=DIRECTION('',(0.,-1.,0.));
#866=VECTOR('',#865,1.);
#867=CARTESIAN_POINT('',(-71.3000000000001,0.,-1.25));
#868=LINE('',#867,#866);
#869=EDGE_CURVE('E786',#862,#541,#868,.T.);
#870=ORIENTED_EDGE('',*,*,#869,.T.);
#871=ORIENTED_EDGE('',*,*,#542,.F.);
#872=EDGE_LOOP('',(#855,#864,#870,#871));
#873=FACE_BOUND('',#872,.T.);
#874=ADVANCED_FACE('F1256',(#873),#847,.F.);
#875=CARTESIAN_POINT('',(-73.0000000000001,16.,-2.75));
#876=DIRECTION('',(0.,1.,0.));
#877=DIRECTION('',(0.,0.,1.));
#878=AXIS2_PLACEMENT_3D('',#875,#876,#877);
#879=CYLINDRICAL_SURFACE('',#878,1.69999999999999);
#880=DIRECTION('',(0.,-1.,0.));
#881=VECTOR('',#880,1.);
#882=CARTESIAN_POINT('',(-71.3000000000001,0.,-2.75));
#883=LINE('',#882,#881);
#884=CARTESIAN_POINT('',(-71.3000000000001,12.6,-2.75));
#885=VERTEX_POINT('',#884);
#886=EDGE_CURVE('E810',#885,#522,#883,.T.);
#887=ORIENTED_EDGE('',*,*,#886,.F.);
#888=CARTESIAN_POINT('',(-73.0000000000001,12.6,-2.75));
#889=DIRECTION('',(0.,1.,0.));
#890=DIRECTION('',(0.,0.,1.));
#891=AXIS2_PLACEMENT_3D('',#888,#889,#890);
#892=CIRCLE('',#891,1.69999999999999);
#893=CARTESIAN_POINT('',(-74.7000000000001,12.6,-2.75));
#894=VERTEX_POINT('',#893);
#895=EDGE_CURVE('E821',#885,#894,#892,.T.);
#896=ORIENTED_EDGE('',*,*,#895,.T.);
#897=DIRECTION('',(0.,1.,0.));
#898=VECTOR('',#897,1.);
#899=CARTESIAN_POINT('',(-74.7000000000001,16.,-2.75));
#900=LINE('',#899,#898);
#901=EDGE_CURVE('E803',#524,#894,#900,.T.);
#902=ORIENTED_EDGE('',*,*,#901,.F.);
#903=ORIENTED_EDGE('',*,*,#525,.F.);
#904=EDGE_LOOP('',(#887,#896,#902,#903));
#905=FACE_BOUND('',#904,.T.);
#906=ADVANCED_FACE('F1246',(#905),#879,.F.);
#907=CARTESIAN_POINT('',(-74.7000000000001,16.,-1.25));
#908=DIRECTION('',(-1.,0.,0.));
#909=DIRECTION('',(0.,0.,1.));
#910=AXIS2_PLACEMENT_3D('',#907,#908,#909);
#911=PLANE('',#910);
#912=ORIENTED_EDGE('',*,*,#901,.T.);
#913=DIRECTION('',(0.,0.,-1.));
#914=VECTOR('',#913,1.);
#915=CARTESIAN_POINT('',(-74.7000000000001,12.6,-1.25));
#916=LINE('',#915,#914);
#917=EDGE_CURVE('E767',#853,#894,#916,.T.);
#918=ORIENTED_EDGE('',*,*,#917,.F.);
#919=ORIENTED_EDGE('',*,*,#854,.T.);
#920=ORIENTED_EDGE('',*,*,#533,.F.);
#921=EDGE_LOOP('',(#912,#918,#919,#920));
#922=FACE_BOUND('',#921,.T.);
#923=ADVANCED_FACE('F1242',(#922),#911,.F.);
#924=CARTESIAN_POINT('',(-71.3000000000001,0.,-1.25));
#925=DIRECTION('',(1.,0.,0.));
#926=DIRECTION('',(0.,1.,0.));
#927=AXIS2_PLACEMENT_3D('',#924,#925,#926);
#928=PLANE('',#927);
#929=ORIENTED_EDGE('',*,*,#869,.F.);
#930=DIRECTION('',(0.,0.,-1.));
#931=VECTOR('',#930,1.);
#932=CARTESIAN_POINT('',(-71.3000000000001,12.6,-1.25));
#933=LINE('',#932,#931);
#934=EDGE_CURVE('E764',#862,#885,#933,.T.);
#935=ORIENTED_EDGE('',*,*,#934,.T.);
#936=ORIENTED_EDGE('',*,*,#886,.T.);
#937=ORIENTED_EDGE('',*,*,#548,.F.);
#938=EDGE_LOOP('',(#929,#935,#936,#937));
#939=FACE_BOUND('',#938,.T.);
#940=ADVANCED_FACE('F1238',(#939),#928,.F.);
#941=CARTESIAN_POINT('',(-71.3000000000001,12.6,-2.75));
#942=DIRECTION('',(0.,-1.,0.));
#943=DIRECTION('',(0.,0.,-1.));
#944=AXIS2_PLACEMENT_3D('',#941,#942,#943);
#945=PLANE('',#944);
#946=DIRECTION('',(0.,0.,-1.));
#947=VECTOR('',#946,1.);
#948=CARTESIAN_POINT('',(-76.2500000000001,12.6,-1.25));
#949=LINE('',#948,#947);
#950=CARTESIAN_POINT('',(-76.2500000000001,12.6,-1.25));
#951=VERTEX_POINT('',#950);
#952=CARTESIAN_POINT('',(-76.2500000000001,12.6,-2.75));
#953=VERTEX_POINT('',#952);
#954=EDGE_CURVE('E771',#951,#953,#949,.T.);
#955=ORIENTED_EDGE('',*,*,#954,.F.);
#956=CARTESIAN_POINT('',(-73.0000000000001,12.6,-1.25));
#957=DIRECTION('',(0.,1.,0.));
#958=DIRECTION('',(0.,0.,1.));
#959=AXIS2_PLACEMENT_3D('',#956,#957,#958);
#960=CIRCLE('',#959,3.25);
#961=CARTESIAN_POINT('',(-69.7500000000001,12.6,-1.25));
#962=VERTEX_POINT('',#961);
#963=EDGE_CURVE('E794',#951,#962,#960,.T.);
#964=ORIENTED_EDGE('',*,*,#963,.T.);
#965=DIRECTION('',(0.,0.,-1.));
#966=VECTOR('',#965,1.);
#967=CARTESIAN_POINT('',(-69.7500000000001,12.6,-1.25));
#968=LINE('',#967,#966);
#969=CARTESIAN_POINT('',(-69.7500000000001,12.6,-2.75));
#970=VERTEX_POINT('',#969);
#971=EDGE_CURVE('E761',#962,#970,#968,.T.);
#972=ORIENTED_EDGE('',*,*,#971,.T.);
#973=CARTESIAN_POINT('',(-73.0000000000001,12.6,-2.75));
#974=DIRECTION('',(0.,1.,0.));
#975=DIRECTION('',(0.,0.,1.));
#976=AXIS2_PLACEMENT_3D('',#973,#974,#975);
#977=CIRCLE('',#976,3.25);
#978=EDGE_CURVE('E817',#970,#953,#977,.T.);
#979=ORIENTED_EDGE('',*,*,#978,.T.);
#980=EDGE_LOOP('',(#955,#964,#972,#979));
#981=FACE_BOUND('',#980,.T.);
#982=ORIENTED_EDGE('',*,*,#895,.F.);
#983=ORIENTED_EDGE('',*,*,#934,.F.);
#984=ORIENTED_EDGE('',*,*,#863,.F.);
#985=ORIENTED_EDGE('',*,*,#917,.T.);
#986=EDGE_LOOP('',(#982,#983,#984,#985));
#987=FACE_BOUND('',#986,.T.);
#988=ADVANCED_FACE('F1241',(#981,#987),#945,.F.);
#989=CARTESIAN_POINT('',(-73.0000000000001,16.,-2.75));
#990=DIRECTION('',(0.,1.,0.));
#991=DIRECTION('',(0.,0.,1.));
#992=AXIS2_PLACEMENT_3D('',#989,#990,#991);
#993=CYLINDRICAL_SURFACE('',#992,3.25);
#994=ORIENTED_EDGE('',*,*,#978,.F.);
#995=DIRECTION('',(0.,-1.,0.));
#996=VECTOR('',#995,1.);
#997=CARTESIAN_POINT('',(-69.7500000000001,12.6,-2.75));
#998=LINE('',#997,#996);
#999=EDGE_CURVE('E806',#171,#970,#998,.T.);
#1000=ORIENTED_EDGE('',*,*,#999,.F.);
#1001=ORIENTED_EDGE('',*,*,#172,.T.);
#1002=DIRECTION('',(0.,1.,0.));
#1003=VECTOR('',#1002,1.);
#1004=CARTESIAN_POINT('',(-76.2500000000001,16.,-2.75));
#1005=LINE('',#1004,#1003);
#1006=EDGE_CURVE('E825',#953,#162,#1005,.T.);
#1007=ORIENTED_EDGE('',*,*,#1006,.F.);
#1008=EDGE_LOOP('',(#994,#1000,#1001,#1007));
#1009=FACE_BOUND('',#1008,.T.);
#1010=ADVANCED_FACE('F1254',(#1009),#993,.F.);
#1011=CARTESIAN_POINT('',(-73.0000000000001,16.,-1.25));
#1012=DIRECTION('',(0.,1.,0.));
#1013=DIRECTION('',(0.,0.,1.));
#1014=AXIS2_PLACEMENT_3D('',#1011,#1012,#1013);
#1015=CYLINDRICAL_SURFACE('',#1014,3.25);
#1016=ORIENTED_EDGE('',*,*,#155,.T.);
#1017=DIRECTION('',(0.,-1.,0.));
#1018=VECTOR('',#1017,1.);
#1019=CARTESIAN_POINT('',(-69.7500000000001,12.6,-1.25));
#1020=LINE('',#1019,#1018);
#1021=EDGE_CURVE('E782',#154,#962,#1020,.T.);
#1022=ORIENTED_EDGE('',*,*,#1021,.T.);
#1023=ORIENTED_EDGE('',*,*,#963,.F.);
#1024=DIRECTION('',(0.,1.,0.));
#1025=VECTOR('',#1024,1.);
#1026=CARTESIAN_POINT('',(-76.2500000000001,16.,-1.25));
#1027=LINE('',#1026,#1025);
#1028=EDGE_CURVE('E800',#152,#951,#1027,.F.);
#1029=ORIENTED_EDGE('',*,*,#1028,.F.);
#1030=EDGE_LOOP('',(#1016,#1022,#1023,#1029));
#1031=FACE_BOUND('',#1030,.T.);
#1032=ADVANCED_FACE('F1250',(#1031),#1015,.F.);
#1033=CARTESIAN_POINT('',(-76.2500000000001,16.,-1.25));
#1034=DIRECTION('',(-1.,0.,0.));
#1035=DIRECTION('',(0.,0.,1.));
#1036=AXIS2_PLACEMENT_3D('',#1033,#1034,#1035);
#1037=PLANE('',#1036);
#1038=ORIENTED_EDGE('',*,*,#1006,.T.);
#1039=ORIENTED_EDGE('',*,*,#163,.F.);
#1040=ORIENTED_EDGE('',*,*,#1028,.T.);
#1041=ORIENTED_EDGE('',*,*,#954,.T.);
#1042=EDGE_LOOP('',(#1038,#1039,#1040,#1041));
#1043=FACE_BOUND('',#1042,.T.);
#1044=ADVANCED_FACE('F1236',(#1043),#1037,.F.);
#1045=CARTESIAN_POINT('',(-69.7500000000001,12.6,-1.25));
#1046=DIRECTION('',(1.,0.,0.));
#1047=DIRECTION('',(0.,0.,-1.));
#1048=AXIS2_PLACEMENT_3D('',#1045,#1046,#1047);
#1049=PLANE('',#1048);
#1050=ORIENTED_EDGE('',*,*,#999,.T.);
#1051=ORIENTED_EDGE('',*,*,#971,.F.);
#1052=ORIENTED_EDGE('',*,*,#1021,.F.);
#1053=ORIENTED_EDGE('',*,*,#178,.T.);
#1054=EDGE_LOOP('',(#1050,#1051,#1052,#1053));
#1055=FACE_BOUND('',#1054,.T.);
#1056=ADVANCED_FACE('F1223',(#1055),#1049,.F.);
#1057=CARTESIAN_POINT('',(-193.,16.,-1.24999999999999));
#1058=DIRECTION('',(0.,1.,0.));
#1059=DIRECTION('',(0.,0.,1.));
#1060=AXIS2_PLACEMENT_3D('',#1057,#1058,#1059);
#1061=CYLINDRICAL_SURFACE('',#1060,1.70000000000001);
#1062=DIRECTION('',(0.,1.,0.));
#1063=VECTOR('',#1062,1.);
#1064=CARTESIAN_POINT('',(-194.7,16.,-1.24999999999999));
#1065=LINE('',#1064,#1063);
#1066=CARTESIAN_POINT('',(-194.7,12.6,-1.24999999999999));
#1067=VERTEX_POINT('',#1066);
#1068=EDGE_CURVE('E708',#1067,#496,#1065,.F.);
#1069=ORIENTED_EDGE('',*,*,#1068,.F.);
#1070=CARTESIAN_POINT('',(-193.,12.6,-1.24999999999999));
#1071=DIRECTION('',(0.,1.,0.));
#1072=DIRECTION('',(0.,0.,1.));
#1073=AXIS2_PLACEMENT_3D('',#1070,#1071,#1072);
#1074=CIRCLE('',#1073,1.70000000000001);
#1075=CARTESIAN_POINT('',(-191.3,12.6,-1.24999999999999));
#1076=VERTEX_POINT('',#1075);
#1077=EDGE_CURVE('E727',#1067,#1076,#1074,.T.);
#1078=ORIENTED_EDGE('',*,*,#1077,.T.);
#1079=DIRECTION('',(0.,-1.,0.));
#1080=VECTOR('',#1079,1.);
#1081=CARTESIAN_POINT('',(-191.3,0.,-1.24999999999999));
#1082=LINE('',#1081,#1080);
#1083=EDGE_CURVE('E716',#1076,#505,#1082,.T.);
#1084=ORIENTED_EDGE('',*,*,#1083,.T.);
#1085=ORIENTED_EDGE('',*,*,#506,.F.);
#1086=EDGE_LOOP('',(#1069,#1078,#1084,#1085));
#1087=FACE_BOUND('',#1086,.T.);
#1088=ADVANCED_FACE('F1220',(#1087),#1061,.F.);
#1089=CARTESIAN_POINT('',(-193.,16.,-2.74999999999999));
#1090=DIRECTION('',(0.,1.,0.));
#1091=DIRECTION('',(0.,0.,1.));
#1092=AXIS2_PLACEMENT_3D('',#1089,#1090,#1091);
#1093=CYLINDRICAL_SURFACE('',#1092,1.70000000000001);
#1094=DIRECTION('',(0.,-1.,0.));
#1095=VECTOR('',#1094,1.);
#1096=CARTESIAN_POINT('',(-191.3,0.,-2.74999999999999));
#1097=LINE('',#1096,#1095);
#1098=CARTESIAN_POINT('',(-191.3,12.6,-2.74999999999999));
#1099=VERTEX_POINT('',#1098);
#1100=EDGE_CURVE('E740',#1099,#486,#1097,.T.);
#1101=ORIENTED_EDGE('',*,*,#1100,.F.);
#1102=CARTESIAN_POINT('',(-193.,12.6,-2.74999999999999));
#1103=DIRECTION('',(0.,1.,0.));
#1104=DIRECTION('',(0.,0.,1.));
#1105=AXIS2_PLACEMENT_3D('',#1102,#1103,#1104);
#1106=CIRCLE('',#1105,1.70000000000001);
#1107=CARTESIAN_POINT('',(-194.7,12.6,-2.74999999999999));
#1108=VERTEX_POINT('',#1107);
#1109=EDGE_CURVE('E751',#1099,#1108,#1106,.T.);
#1110=ORIENTED_EDGE('',*,*,#1109,.T.);
#1111=DIRECTION('',(0.,1.,0.));
#1112=VECTOR('',#1111,1.);
#1113=CARTESIAN_POINT('',(-194.7,16.,-2.74999999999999));
#1114=LINE('',#1113,#1112);
#1115=EDGE_CURVE('E733',#488,#1108,#1114,.T.);
#1116=ORIENTED_EDGE('',*,*,#1115,.F.);
#1117=ORIENTED_EDGE('',*,*,#489,.F.);
#1118=EDGE_LOOP('',(#1101,#1110,#1116,#1117));
#1119=FACE_BOUND('',#1118,.T.);
#1120=ADVANCED_FACE('F1210',(#1119),#1093,.F.);
#1121=CARTESIAN_POINT('',(-194.7,16.,-1.24999999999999));
#1122=DIRECTION('',(-1.,0.,0.));
#1123=DIRECTION('',(0.,0.,1.));
#1124=AXIS2_PLACEMENT_3D('',#1121,#1122,#1123);
#1125=PLANE('',#1124);
#1126=ORIENTED_EDGE('',*,*,#1115,.T.);
#1127=DIRECTION('',(0.,0.,-1.));
#1128=VECTOR('',#1127,1.);
#1129=CARTESIAN_POINT('',(-194.7,12.6,-1.24999999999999));
#1130=LINE('',#1129,#1128);
#1131=EDGE_CURVE('E697',#1067,#1108,#1130,.T.);
#1132=ORIENTED_EDGE('',*,*,#1131,.F.);
#1133=ORIENTED_EDGE('',*,*,#1068,.T.);
#1134=ORIENTED_EDGE('',*,*,#497,.F.);
#1135=EDGE_LOOP('',(#1126,#1132,#1133,#1134));
#1136=FACE_BOUND('',#1135,.T.);
#1137=ADVANCED_FACE('F1206',(#1136),#1125,.F.);
#1138=CARTESIAN_POINT('',(-191.3,0.,-1.24999999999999));
#1139=DIRECTION('',(1.,0.,0.));
#1140=DIRECTION('',(0.,1.,0.));
#1141=AXIS2_PLACEMENT_3D('',#1138,#1139,#1140);
#1142=PLANE('',#1141);
#1143=ORIENTED_EDGE('',*,*,#1083,.F.);
#1144=DIRECTION('',(0.,0.,-1.));
#1145=VECTOR('',#1144,1.);
#1146=CARTESIAN_POINT('',(-191.3,12.6,-1.24999999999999));
#1147=LINE('',#1146,#1145);
#1148=EDGE_CURVE('E694',#1076,#1099,#1147,.T.);
#1149=ORIENTED_EDGE('',*,*,#1148,.T.);
#1150=ORIENTED_EDGE('',*,*,#1100,.T.);
#1151=ORIENTED_EDGE('',*,*,#512,.F.);
#1152=EDGE_LOOP('',(#1143,#1149,#1150,#1151));
#1153=FACE_BOUND('',#1152,.T.);
#1154=ADVANCED_FACE('F1202',(#1153),#1142,.F.);
#1155=CARTESIAN_POINT('',(-191.3,12.6,-2.74999999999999));
#1156=DIRECTION('',(0.,-1.,0.));
#1157=DIRECTION('',(0.,0.,-1.));
#1158=AXIS2_PLACEMENT_3D('',#1155,#1156,#1157);
#1159=PLANE('',#1158);
#1160=DIRECTION('',(0.,0.,-1.));
#1161=VECTOR('',#1160,1.);
#1162=CARTESIAN_POINT('',(-196.25,12.6,-1.24999999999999));
#1163=LINE('',#1162,#1161);
#1164=CARTESIAN_POINT('',(-196.25,12.6,-1.24999999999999));
#1165=VERTEX_POINT('',#1164);
#1166=CARTESIAN_POINT('',(-196.25,12.6,-2.74999999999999));
#1167=VERTEX_POINT('',#1166);
#1168=EDGE_CURVE('E701',#1165,#1167,#1163,.T.);
#1169=ORIENTED_EDGE('',*,*,#1168,.F.);
#1170=CARTESIAN_POINT('',(-193.,12.6,-1.24999999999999));
#1171=DIRECTION('',(0.,1.,0.));
#1172=DIRECTION('',(0.,0.,1.));
#1173=AXIS2_PLACEMENT_3D('',#1170,#1171,#1172);
#1174=CIRCLE('',#1173,3.25);
#1175=CARTESIAN_POINT('',(-189.75,12.6,-1.24999999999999));
#1176=VERTEX_POINT('',#1175);
#1177=EDGE_CURVE('E724',#1165,#1176,#1174,.T.);
#1178=ORIENTED_EDGE('',*,*,#1177,.T.);
#1179=DIRECTION('',(0.,0.,-1.));
#1180=VECTOR('',#1179,1.);
#1181=CARTESIAN_POINT('',(-189.75,12.6,-1.24999999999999));
#1182=LINE('',#1181,#1180);
#1183=CARTESIAN_POINT('',(-189.75,12.6,-2.74999999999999));
#1184=VERTEX_POINT('',#1183);
#1185=EDGE_CURVE('E691',#1176,#1184,#1182,.T.);
#1186=ORIENTED_EDGE('',*,*,#1185,.T.);
#1187=CARTESIAN_POINT('',(-193.,12.6,-2.74999999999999));
#1188=DIRECTION('',(0.,1.,0.));
#1189=DIRECTION('',(0.,0.,1.));
#1190=AXIS2_PLACEMENT_3D('',#1187,#1188,#1189);
#1191=CIRCLE('',#1190,3.25);
#1192=EDGE_CURVE('E747',#1184,#1167,#1191,.T.);
#1193=ORIENTED_EDGE('',*,*,#1192,.T.);
#1194=EDGE_LOOP('',(#1169,#1178,#1186,#1193));
#1195=FACE_BOUND('',#1194,.T.);
#1196=ORIENTED_EDGE('',*,*,#1109,.F.);
#1197=ORIENTED_EDGE('',*,*,#1148,.F.);
#1198=ORIENTED_EDGE('',*,*,#1077,.F.);
#1199=ORIENTED_EDGE('',*,*,#1131,.T.);
#1200=EDGE_LOOP('',(#1196,#1197,#1198,#1199));
#1201=FACE_BOUND('',#1200,.T.);
#1202=ADVANCED_FACE('F1205',(#1195,#1201),#1159,.F.);
#1203=CARTESIAN_POINT('',(-193.,16.,-2.74999999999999));
#1204=DIRECTION('',(0.,1.,0.));
#1205=DIRECTION('',(0.,0.,1.));
#1206=AXIS2_PLACEMENT_3D('',#1203,#1204,#1205);
#1207=CYLINDRICAL_SURFACE('',#1206,3.25);
#1208=ORIENTED_EDGE('',*,*,#1192,.F.);
#1209=DIRECTION('',(0.,-1.,0.));
#1210=VECTOR('',#1209,1.);
#1211=CARTESIAN_POINT('',(-189.75,12.6,-2.74999999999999));
#1212=LINE('',#1211,#1210);
#1213=EDGE_CURVE('E736',#207,#1184,#1212,.T.);
#1214=ORIENTED_EDGE('',*,*,#1213,.F.);
#1215=ORIENTED_EDGE('',*,*,#208,.T.);
#1216=DIRECTION('',(0.,1.,0.));
#1217=VECTOR('',#1216,1.);
#1218=CARTESIAN_POINT('',(-196.25,16.,-2.74999999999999));
#1219=LINE('',#1218,#1217);
#1220=EDGE_CURVE('E755',#1167,#198,#1219,.T.);
#1221=ORIENTED_EDGE('',*,*,#1220,.F.);
#1222=EDGE_LOOP('',(#1208,#1214,#1215,#1221));
#1223=FACE_BOUND('',#1222,.T.);
#1224=ADVANCED_FACE('F1218',(#1223),#1207,.F.);
#1225=CARTESIAN_POINT('',(-193.,16.,-1.24999999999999));
#1226=DIRECTION('',(0.,1.,0.));
#1227=DIRECTION('',(0.,0.,1.));
#1228=AXIS2_PLACEMENT_3D('',#1225,#1226,#1227);
#1229=CYLINDRICAL_SURFACE('',#1228,3.25);
#1230=ORIENTED_EDGE('',*,*,#191,.T.);
#1231=DIRECTION('',(0.,-1.,0.));
#1232=VECTOR('',#1231,1.);
#1233=CARTESIAN_POINT('',(-189.75,12.6,-1.24999999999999));
#1234=LINE('',#1233,#1232);
#1235=EDGE_CURVE('E712',#190,#1176,#1234,.T.);
#1236=ORIENTED_EDGE('',*,*,#1235,.T.);
#1237=ORIENTED_EDGE('',*,*,#1177,.F.);
#1238=DIRECTION('',(0.,1.,0.));
#1239=VECTOR('',#1238,1.);
#1240=CARTESIAN_POINT('',(-196.25,16.,-1.24999999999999));
#1241=LINE('',#1240,#1239);
#1242=EDGE_CURVE('E730',#188,#1165,#1241,.F.);
#1243=ORIENTED_EDGE('',*,*,#1242,.F.);
#1244=EDGE_LOOP('',(#1230,#1236,#1237,#1243));
#1245=FACE_BOUND('',#1244,.T.);
#1246=ADVANCED_FACE('F1214',(#1245),#1229,.F.);
#1247=CARTESIAN_POINT('',(-196.25,16.,-1.24999999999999));
#1248=DIRECTION('',(-1.,0.,0.));
#1249=DIRECTION('',(0.,0.,1.));
#1250=AXIS2_PLACEMENT_3D('',#1247,#1248,#1249);
#1251=PLANE('',#1250);
#1252=ORIENTED_EDGE('',*,*,#1220,.T.);
#1253=ORIENTED_EDGE('',*,*,#199,.F.);
#1254=ORIENTED_EDGE('',*,*,#1242,.T.);
#1255=ORIENTED_EDGE('',*,*,#1168,.T.);
#1256=EDGE_LOOP('',(#1252,#1253,#1254,#1255));
#1257=FACE_BOUND('',#1256,.T.);
#1258=ADVANCED_FACE('F1200',(#1257),#1251,.F.);
#1259=CARTESIAN_POINT('',(-189.75,12.6,-1.24999999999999));
#1260=DIRECTION('',(1.,0.,0.));
#1261=DIRECTION('',(0.,0.,-1.));
#1262=AXIS2_PLACEMENT_3D('',#1259,#1260,#1261);
#1263=PLANE('',#1262);
#1264=ORIENTED_EDGE('',*,*,#1213,.T.);
#1265=ORIENTED_EDGE('',*,*,#1185,.F.);
#1266=ORIENTED_EDGE('',*,*,#1235,.F.);
#1267=ORIENTED_EDGE('',*,*,#214,.T.);
#1268=EDGE_LOOP('',(#1264,#1265,#1266,#1267));
#1269=FACE_BOUND('',#1268,.T.);
#1270=ADVANCED_FACE('F1177',(#1269),#1263,.F.);
#1271=CARTESIAN_POINT('',(194.7,0.,-1.25));
#1272=DIRECTION('',(1.,0.,0.));
#1273=DIRECTION('',(0.,1.,0.));
#1274=AXIS2_PLACEMENT_3D('',#1271,#1272,#1273);
#1275=PLANE('',#1274);
#1276=DIRECTION('',(0.,-1.,0.));
#1277=VECTOR('',#1276,1.);
#1278=CARTESIAN_POINT('',(194.7,0.,-1.25));
#1279=LINE('',#1278,#1277);
#1280=CARTESIAN_POINT('',(194.7,12.6,-1.25));
#1281=VERTEX_POINT('',#1280);
#1282=EDGE_CURVE('E646',#1281,#452,#1279,.T.);
#1283=ORIENTED_EDGE('',*,*,#1282,.F.);
#1284=DIRECTION('',(0.,0.,-1.));
#1285=VECTOR('',#1284,1.);
#1286=CARTESIAN_POINT('',(194.7,12.6,-1.25));
#1287=LINE('',#1286,#1285);
#1288=CARTESIAN_POINT('',(194.7,12.6,-2.75));
#1289=VERTEX_POINT('',#1288);
#1290=EDGE_CURVE('E639',#1281,#1289,#1287,.T.);
#1291=ORIENTED_EDGE('',*,*,#1290,.T.);
#1292=DIRECTION('',(0.,-1.,0.));
#1293=VECTOR('',#1292,1.);
#1294=CARTESIAN_POINT('',(194.7,0.,-2.75));
#1295=LINE('',#1294,#1293);
#1296=EDGE_CURVE('E670',#1289,#460,#1295,.T.);
#1297=ORIENTED_EDGE('',*,*,#1296,.T.);
#1298=ORIENTED_EDGE('',*,*,#461,.F.);
#1299=EDGE_LOOP('',(#1283,#1291,#1297,#1298));
#1300=FACE_BOUND('',#1299,.T.);
#1301=ADVANCED_FACE('F1173',(#1300),#1275,.F.);
#1302=CARTESIAN_POINT('',(193.,16.,-2.75));
#1303=DIRECTION('',(0.,1.,0.));
#1304=DIRECTION('',(0.,0.,1.));
#1305=AXIS2_PLACEMENT_3D('',#1302,#1303,#1304);
#1306=CYLINDRICAL_SURFACE('',#1305,1.70000000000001);
#1307=ORIENTED_EDGE('',*,*,#1296,.F.);
#1308=CARTESIAN_POINT('',(193.,12.6,-2.75));
#1309=DIRECTION('',(0.,1.,0.));
#1310=DIRECTION('',(0.,0.,1.));
#1311=AXIS2_PLACEMENT_3D('',#1308,#1309,#1310);
#1312=CIRCLE('',#1311,1.70000000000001);
#1313=CARTESIAN_POINT('',(191.3,12.6,-2.75));
#1314=VERTEX_POINT('',#1313);
#1315=EDGE_CURVE('E681',#1289,#1314,#1312,.T.);
#1316=ORIENTED_EDGE('',*,*,#1315,.T.);
#1317=DIRECTION('',(0.,1.,0.));
#1318=VECTOR('',#1317,1.);
#1319=CARTESIAN_POINT('',(191.3,16.,-2.75));
#1320=LINE('',#1319,#1318);
#1321=EDGE_CURVE('E665',#469,#1314,#1320,.T.);
#1322=ORIENTED_EDGE('',*,*,#1321,.F.);
#1323=ORIENTED_EDGE('',*,*,#470,.F.);
#1324=EDGE_LOOP('',(#1307,#1316,#1322,#1323));
#1325=FACE_BOUND('',#1324,.T.);
#1326=ADVANCED_FACE('F1176',(#1325),#1306,.F.);
#1327=CARTESIAN_POINT('',(193.,16.,-1.25));
#1328=DIRECTION('',(0.,1.,0.));
#1329=DIRECTION('',(0.,0.,1.));
#1330=AXIS2_PLACEMENT_3D('',#1327,#1328,#1329);
#1331=CYLINDRICAL_SURFACE('',#1330,1.70000000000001);
#1332=DIRECTION('',(0.,1.,0.));
#1333=VECTOR('',#1332,1.);
#1334=CARTESIAN_POINT('',(191.3,16.,-1.25));
#1335=LINE('',#1334,#1333);
#1336=CARTESIAN_POINT('',(191.3,12.6,-1.25));
#1337=VERTEX_POINT('',#1336);
#1338=EDGE_CURVE('E647',#1337,#450,#1335,.F.);
#1339=ORIENTED_EDGE('',*,*,#1338,.F.);
#1340=CARTESIAN_POINT('',(193.,12.6,-1.25));
#1341=DIRECTION('',(0.,1.,0.));
#1342=DIRECTION('',(0.,0.,1.));
#1343=AXIS2_PLACEMENT_3D('',#1340,#1341,#1342);
#1344=CIRCLE('',#1343,1.70000000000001);
#1345=EDGE_CURVE('E628',#1337,#1281,#1344,.T.);
#1346=ORIENTED_EDGE('',*,*,#1345,.T.);
#1347=ORIENTED_EDGE('',*,*,#1282,.T.);
#1348=ORIENTED_EDGE('',*,*,#453,.F.);
#1349=EDGE_LOOP('',(#1339,#1346,#1347,#1348));
#1350=FACE_BOUND('',#1349,.T.);
#1351=ADVANCED_FACE('F1181',(#1350),#1331,.F.);
#1352=CARTESIAN_POINT('',(191.3,16.,-1.25));
#1353=DIRECTION('',(-1.,0.,0.));
#1354=DIRECTION('',(0.,0.,1.));
#1355=AXIS2_PLACEMENT_3D('',#1352,#1353,#1354);
#1356=PLANE('',#1355);
#1357=ORIENTED_EDGE('',*,*,#1321,.T.);
#1358=DIRECTION('',(0.,0.,-1.));
#1359=VECTOR('',#1358,1.);
#1360=CARTESIAN_POINT('',(191.3,12.6,-1.25));
#1361=LINE('',#1360,#1359);
#1362=EDGE_CURVE('E1347',#1337,#1314,#1361,.T.);
#1363=ORIENTED_EDGE('',*,*,#1362,.F.);
#1364=ORIENTED_EDGE('',*,*,#1338,.T.);
#1365=ORIENTED_EDGE('',*,*,#476,.F.);
#1366=EDGE_LOOP('',(#1357,#1363,#1364,#1365));
#1367=FACE_BOUND('',#1366,.T.);
#1368=ADVANCED_FACE('F1179',(#1367),#1356,.F.);
#1369=CARTESIAN_POINT('',(194.7,12.6,-2.75));
#1370=DIRECTION('',(0.,-1.,0.));
#1371=DIRECTION('',(0.,0.,-1.));
#1372=AXIS2_PLACEMENT_3D('',#1369,#1370,#1371);
#1373=PLANE('',#1372);
#1374=DIRECTION('',(0.,0.,-1.));
#1375=VECTOR('',#1374,1.);
#1376=CARTESIAN_POINT('',(189.75,12.6,-1.25));
#1377=LINE('',#1376,#1375);
#1378=CARTESIAN_POINT('',(189.75,12.6,-1.25));
#1379=VERTEX_POINT('',#1378);
#1380=CARTESIAN_POINT('',(189.75,12.6,-2.75));
#1381=VERTEX_POINT('',#1380);
#1382=EDGE_CURVE('E623',#1379,#1381,#1377,.T.);
#1383=ORIENTED_EDGE('',*,*,#1382,.F.);
#1384=CARTESIAN_POINT('',(193.,12.6,-1.25));
#1385=DIRECTION('',(0.,1.,0.));
#1386=DIRECTION('',(0.,0.,1.));
#1387=AXIS2_PLACEMENT_3D('',#1384,#1385,#1386);
#1388=CIRCLE('',#1387,3.25);
#1389=CARTESIAN_POINT('',(196.25,12.6,-1.25));
#1390=VERTEX_POINT('',#1389);
#1391=EDGE_CURVE('E616',#1379,#1390,#1388,.T.);
#1392=ORIENTED_EDGE('',*,*,#1391,.T.);
#1393=DIRECTION('',(0.,0.,-1.));
#1394=VECTOR('',#1393,1.);
#1395=CARTESIAN_POINT('',(196.25,12.6,-1.25));
#1396=LINE('',#1395,#1394);
#1397=CARTESIAN_POINT('',(196.25,12.6,-2.75));
#1398=VERTEX_POINT('',#1397);
#1399=EDGE_CURVE('E621',#1390,#1398,#1396,.T.);
#1400=ORIENTED_EDGE('',*,*,#1399,.T.);
#1401=CARTESIAN_POINT('',(193.,12.6,-2.75));
#1402=DIRECTION('',(0.,1.,0.));
#1403=DIRECTION('',(0.,0.,1.));
#1404=AXIS2_PLACEMENT_3D('',#1401,#1402,#1403);
#1405=CIRCLE('',#1404,3.25);
#1406=EDGE_CURVE('E678',#1398,#1381,#1405,.T.);
#1407=ORIENTED_EDGE('',*,*,#1406,.T.);
#1408=EDGE_LOOP('',(#1383,#1392,#1400,#1407));
#1409=FACE_BOUND('',#1408,.T.);
#1410=ORIENTED_EDGE('',*,*,#1315,.F.);
#1411=ORIENTED_EDGE('',*,*,#1290,.F.);
#1412=ORIENTED_EDGE('',*,*,#1345,.F.);
#1413=ORIENTED_EDGE('',*,*,#1362,.T.);
#1414=EDGE_LOOP('',(#1410,#1411,#1412,#1413));
#1415=FACE_BOUND('',#1414,.T.);
#1416=ADVANCED_FACE('F618',(#1409,#1415),#1373,.F.);
#1417=CARTESIAN_POINT('',(193.,16.,-2.75));
#1418=DIRECTION('',(0.,1.,0.));
#1419=DIRECTION('',(0.,0.,1.));
#1420=AXIS2_PLACEMENT_3D('',#1417,#1418,#1419);
#1421=CYLINDRICAL_SURFACE('',#1420,3.25);
#1422=ORIENTED_EDGE('',*,*,#1406,.F.);
#1423=DIRECTION('',(0.,-1.,0.));
#1424=VECTOR('',#1423,1.);
#1425=CARTESIAN_POINT('',(196.25,12.6,-2.75));
#1426=LINE('',#1425,#1424);
#1427=EDGE_CURVE('E637',#40,#1398,#1426,.T.);
#1428=ORIENTED_EDGE('',*,*,#1427,.F.);
#1429=ORIENTED_EDGE('',*,*,#41,.T.);
#1430=DIRECTION('',(0.,1.,0.));
#1431=VECTOR('',#1430,1.);
#1432=CARTESIAN_POINT('',(189.75,16.,-2.75));
#1433=LINE('',#1432,#1431);
#1434=EDGE_CURVE('E685',#1381,#31,#1433,.T.);
#1435=ORIENTED_EDGE('',*,*,#1434,.F.);
#1436=EDGE_LOOP('',(#1422,#1428,#1429,#1435));
#1437=FACE_BOUND('',#1436,.T.);
#1438=ADVANCED_FACE('F1186',(#1437),#1421,.F.);
#1439=CARTESIAN_POINT('',(193.,16.,-1.25));
#1440=DIRECTION('',(0.,1.,0.));
#1441=DIRECTION('',(0.,0.,1.));
#1442=AXIS2_PLACEMENT_3D('',#1439,#1440,#1441);
#1443=CYLINDRICAL_SURFACE('',#1442,3.25);
#1444=ORIENTED_EDGE('',*,*,#56,.T.);
#1445=DIRECTION('',(0.,-1.,0.));
#1446=VECTOR('',#1445,1.);
#1447=CARTESIAN_POINT('',(196.25,12.6,-1.25));
#1448=LINE('',#1447,#1446);
#1449=EDGE_CURVE('E634',#48,#1390,#1448,.T.);
#1450=ORIENTED_EDGE('',*,*,#1449,.T.);
#1451=ORIENTED_EDGE('',*,*,#1391,.F.);
#1452=DIRECTION('',(0.,1.,0.));
#1453=VECTOR('',#1452,1.);
#1454=CARTESIAN_POINT('',(189.75,16.,-1.25));
#1455=LINE('',#1454,#1453);
#1456=EDGE_CURVE('E662',#29,#1379,#1455,.F.);
#1457=ORIENTED_EDGE('',*,*,#1456,.F.);
#1458=EDGE_LOOP('',(#1444,#1450,#1451,#1457));
#1459=FACE_BOUND('',#1458,.T.);
#1460=ADVANCED_FACE('F642',(#1459),#1443,.F.);
#1461=CARTESIAN_POINT('',(189.75,16.,-1.25));
#1462=DIRECTION('',(-1.,0.,0.));
#1463=DIRECTION('',(0.,0.,1.));
#1464=AXIS2_PLACEMENT_3D('',#1461,#1462,#1463);
#1465=PLANE('',#1464);
#1466=ORIENTED_EDGE('',*,*,#1434,.T.);
#1467=ORIENTED_EDGE('',*,*,#32,.F.);
#1468=ORIENTED_EDGE('',*,*,#1456,.T.);
#1469=ORIENTED_EDGE('',*,*,#1382,.T.);
#1470=EDGE_LOOP('',(#1466,#1467,#1468,#1469));
#1471=FACE_BOUND('',#1470,.T.);
#1472=ADVANCED_FACE('F1165',(#1471),#1465,.F.);
#1473=CARTESIAN_POINT('',(196.25,12.6,-1.25));
#1474=DIRECTION('',(1.,0.,0.));
#1475=DIRECTION('',(0.,0.,-1.));
#1476=AXIS2_PLACEMENT_3D('',#1473,#1474,#1475);
#1477=PLANE('',#1476);
#1478=ORIENTED_EDGE('',*,*,#1427,.T.);
#1479=ORIENTED_EDGE('',*,*,#1399,.F.);
#1480=ORIENTED_EDGE('',*,*,#1449,.F.);
#1481=ORIENTED_EDGE('',*,*,#49,.T.);
#1482=EDGE_LOOP('',(#1478,#1479,#1480,#1481));
#1483=FACE_BOUND('',#1482,.T.);
#1484=ADVANCED_FACE('F633',(#1483),#1477,.F.);
#1485=CARTESIAN_POINT('',(0.,16.,6.00000000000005));
#1486=DIRECTION('',(0.,0.707106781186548,0.707106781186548));
#1487=DIRECTION('',(-1.,0.,0.));
#1488=AXIS2_PLACEMENT_3D('',#1485,#1486,#1487);
#1489=PLANE('',#1488);
#1490=ORIENTED_EDGE('',*,*,#389,.F.);
#1491=DIRECTION('',(-0.577350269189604,-0.577350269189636,0.577350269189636));
#1492=VECTOR('',#1491,1.);
#1493=CARTESIAN_POINT('',(142.666666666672,-55.3333333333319,77.333333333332));
#1494=LINE('',#1493,#1492);
#1495=EDGE_CURVE('E1068',#380,#246,#1494,.F.);
#1496=ORIENTED_EDGE('',*,*,#1495,.T.);
#1497=ORIENTED_EDGE('',*,*,#247,.F.);
#1498=ORIENTED_EDGE('',*,*,#142,.F.);
#1499=ORIENTED_EDGE('',*,*,#332,.F.);
#1500=DIRECTION('',(-0.577350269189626,0.577350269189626,-0.577350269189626));
#1501=VECTOR('',#1500,1.);
#1502=CARTESIAN_POINT('',(-142.666666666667,-55.3333333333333,77.3333333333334));
#1503=LINE('',#1502,#1501);
#1504=EDGE_CURVE('E361',#325,#388,#1503,.F.);
#1505=ORIENTED_EDGE('',*,*,#1504,.T.);
#1506=EDGE_LOOP('',(#1490,#1496,#1497,#1498,#1499,#1505));
#1507=FACE_BOUND('',#1506,.T.);
#1508=ADVANCED_FACE('F1107',(#1507),#1489,.T.);
#1509=CARTESIAN_POINT('',(212.,16.,-8.));
#1510=DIRECTION('',(-0.707106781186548,0.,0.707106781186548));
#1511=DIRECTION('',(0.,-1.,0.));
#1512=AXIS2_PLACEMENT_3D('',#1509,#1510,#1511);
#1513=PLANE('',#1512);
#1514=ORIENTED_EDGE('',*,*,#112,.F.);
#1515=ORIENTED_EDGE('',*,*,#238,.F.);
#1516=ORIENTED_EDGE('',*,*,#593,.F.);
#1517=ORIENTED_EDGE('',*,*,#286,.F.);
#1518=EDGE_LOOP('',(#1514,#1515,#1516,#1517));
#1519=FACE_BOUND('',#1518,.T.);
#1520=ADVANCED_FACE('F1111',(#1519),#1513,.F.);
#1521=CARTESIAN_POINT('',(213.,16.,7.));
#1522=DIRECTION('',(-0.707106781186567,0.,-0.707106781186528));
#1523=DIRECTION('',(0.,-1.,0.));
#1524=AXIS2_PLACEMENT_3D('',#1521,#1522,#1523);
#1525=PLANE('',#1524);
#1526=ORIENTED_EDGE('',*,*,#1495,.F.);
#1527=ORIENTED_EDGE('',*,*,#381,.F.);
#1528=ORIENTED_EDGE('',*,*,#617,.F.);
#1529=ORIENTED_EDGE('',*,*,#255,.F.);
#1530=EDGE_LOOP('',(#1526,#1527,#1528,#1529));
#1531=FACE_BOUND('',#1530,.T.);
#1532=ADVANCED_FACE('F1109',(#1531),#1525,.F.);
#1533=CARTESIAN_POINT('',(-212.,16.,8.));
#1534=DIRECTION('',(0.707106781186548,0.,-0.707106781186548));
#1535=DIRECTION('',(0.,-1.,0.));
#1536=AXIS2_PLACEMENT_3D('',#1533,#1534,#1535);
#1537=PLANE('',#1536);
#1538=ORIENTED_EDGE('',*,*,#1504,.F.);
#1539=ORIENTED_EDGE('',*,*,#326,.F.);
#1540=ORIENTED_EDGE('',*,*,#624,.F.);
#1541=ORIENTED_EDGE('',*,*,#395,.F.);
#1542=EDGE_LOOP('',(#1538,#1539,#1540,#1541));
#1543=FACE_BOUND('',#1542,.T.);
#1544=ADVANCED_FACE('F1102',(#1543),#1537,.F.);
#1545=CARTESIAN_POINT('',(-213.,16.,-7.));
#1546=DIRECTION('',(0.707106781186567,0.,0.707106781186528));
#1547=DIRECTION('',(0.,-1.,0.));
#1548=AXIS2_PLACEMENT_3D('',#1545,#1546,#1547);
#1549=PLANE('',#1548);
#1550=ORIENTED_EDGE('',*,*,#128,.F.);
#1551=ORIENTED_EDGE('',*,*,#300,.F.);
#1552=ORIENTED_EDGE('',*,*,#602,.F.);
#1553=ORIENTED_EDGE('',*,*,#341,.F.);
#1554=EDGE_LOOP('',(#1550,#1551,#1552,#1553));
#1555=FACE_BOUND('',#1554,.T.);
#1556=ADVANCED_FACE('F342',(#1555),#1549,.F.);
#1557=CLOSED_SHELL('',(#218,#273,#304,#359,#399,#421,#438,#606,#628,#660,#684,#709,#726,#774,
#796,#818,#830,#842,#874,#906,#923,#940,#988,#1010,#1032,#1044,#1056,#1088,#1120,#1137,#1154,
#1202,#1224,#1246,#1258,#1270,#1301,#1326,#1351,#1368,#1416,#1438,#1460,#1472,#1484,#1508,#1520,
#1532,#1544,#1556));
#1558=MANIFOLD_SOLID_BREP('B2',#1557);
#1559=ADVANCED_BREP_SHAPE_REPRESENTATION('',(#18,#1558),#14);
#1560=SHAPE_DEFINITION_REPRESENTATION(#9,#1559);
ENDSEC;
END-ISO-10303-21;
